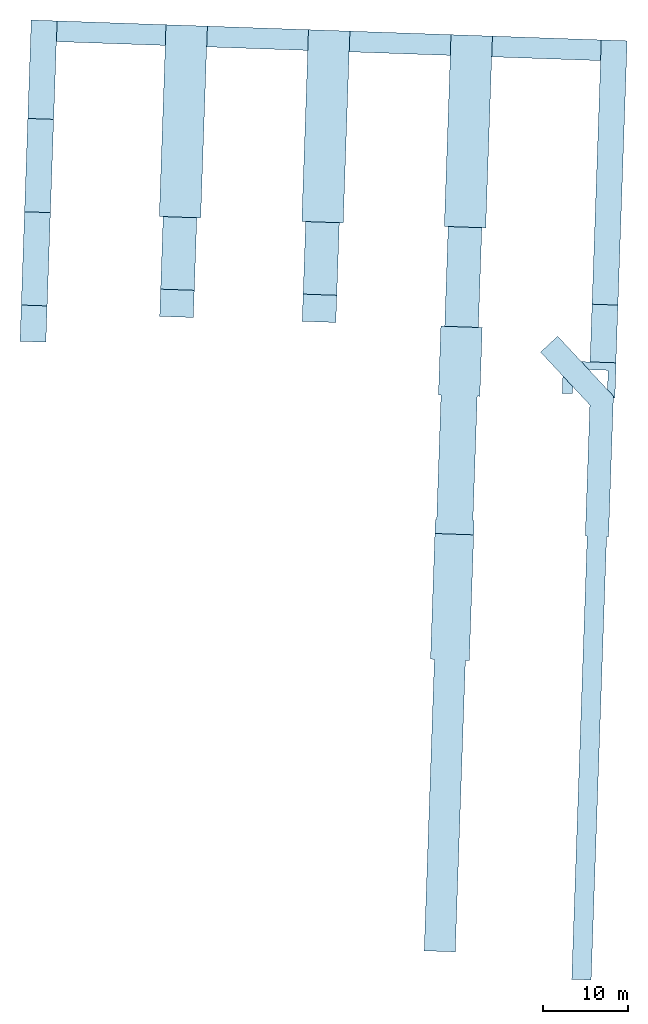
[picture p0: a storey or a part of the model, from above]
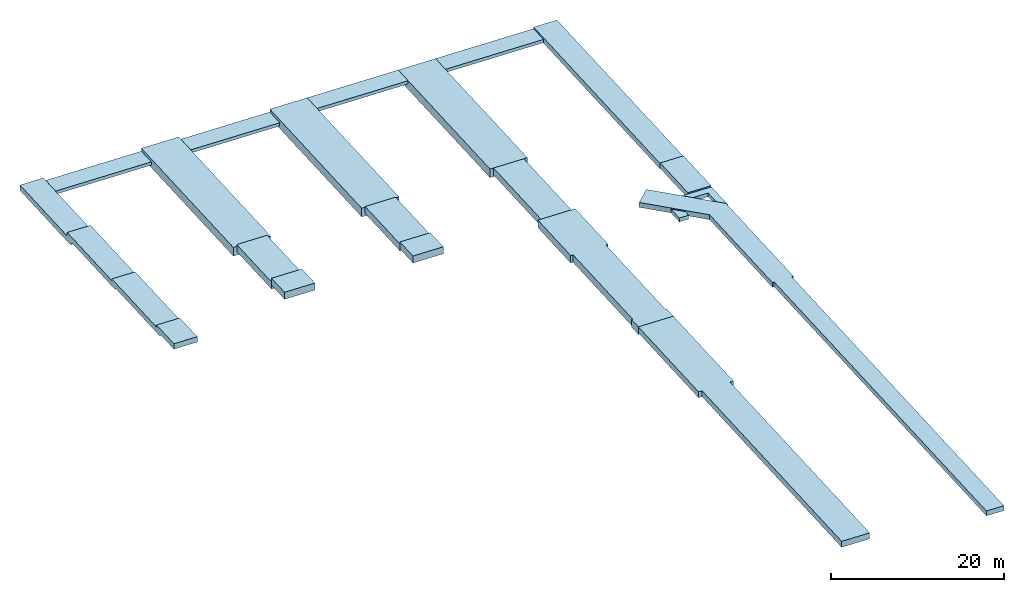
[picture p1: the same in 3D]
Properties of the parts of a building model (IFC2X3), part 1 of 2

# File
Description: ViewDefinition [CoordinationView_V2.0, QuantityTakeOffAddOnView]
File name: 09535.00
Time: 2016-01-25T00:34:02
Written by: The EXPRESS Data Manager Version 5.02.0100.07 : 28 Aug 2013
Made in: 20150702_1515(x64) - Exporter 15.5.0.0 - Alternate UI 15.5.0.0
Comment: STEP Physical File produced by: The EXPRESS Data Manager Version 5.02.0100.07 : 28 Aug 2013 * Module: EDMstepFileFactory/EDMstandAlone * Creation date: Mon Jan 25 00:34:02 2016 * Host: WawanHP * Database: C:\Users\wawan\AppData\Local\Temp\{A744FDD4-6852-4056-9BD2-3EB6C8955B42}\ifc * Database version: 5507 * Database creation date: Mon Jan 25 00:33:48 2016 * Schema: IFC2X3 * Model: DataRepository.ifc * Model creation date: Mon Jan 25 00:33:49 2016 * Header model: DataRepository.ifc_HeaderModel * Header model creation date: Mon Jan 25 00:33:49 2016 * EDMuser: sdai-user * EDMgroup: sdai-group * License ID and type: 5605 : Permanent license. Expiry date: * EDMstepFileFactory options: 020000

# IfcProject, 09535.00
LongName: PROJECT NAME; Phase: Project Status

# IfcSite, Default
RefLatitude: 43, 10, 4, 799999; RefLongitude: -77, -36, -53, -999999; RefElevation: 0.00393701 ft

# IfcBuilding
Pset_BuildingCommon - NumberOfStoreys: 12

# IfcBuildingStorey (12)
Name | LongName | Elevation (ft)
Potential Ground Water Elevation | Potential Ground Water Elevation | 535
Ground Floor | Ground Floor | 543.5
Exist Garage - Ground Level | Exist Garage - Ground Level | 544.75
1st Floor | 1st Floor | 556.833
Existing Garage - 1st Level | Existing Garage - 1st Level | 557
Existing Garage - 2nd Level | Existing Garage - 2nd Level | 567
2nd Floor | 2nd Floor | 570.167
Existing Garage - 3rd Level | Existing Garage - 3rd Level | 577
Existing Garage - 4th Level | Existing Garage - 4th Level | 587
Existing Garage - 5th Level | Existing Garage - 5th Level | 597
Existing Garage - Roof Level | Existing Garage - Roof Level | 607
Exhaust Structure Roof | Exhaust Structure Roof | 617

# IfcSpace (5)
In: Exist Garage - Ground Level
InteriorOrExteriorSpace: INTERNAL
Pset_SpaceCommon - Category: Rooms
Name | LongName | Reference | NetFloorArea (ft2) = GrossFloorArea (ft2) | Height (ft) | GrossPerimeter (ft) | GrossVolume (ft3)
03 | FUEL VAULT | FUEL VAULT 03 | 330 | 10.1894 | 82 | 3362.49
07 | FUEL TANK ROOM #2 | FUEL TANK ROOM #2 07 | 715.313 | 10 | 118.188 | 7153.13
08 | FUEL TANK ROOM #3 | FUEL TANK ROOM #3 08 | 715.313 | 10 | 118.188 | 7153.13
06 | FUEL TANK ROOM #1 | FUEL TANK ROOM #1 06 | 990.656 | 10 | 146.25 | 9906.56
05 | GENERATOR ROOM #2 | GENERATOR ROOM #2 05 | 3270.48 | 10 | 299.545 | 32704.8

# IfcBeam: 05_HSS-Hollow Structural Section:HSS6x6x5/16:1370025 (28)
Classification: B10 Superstructure (Uniformat); Material: Metal - Steel - ASTM A500 - Grade B - Rectangular and Square
BaseQuantities - CrossSectionArea: 0.0446321 ft2
Pset_BeamCommon - LoadBearing: yes; IsExternal: no; Reference: 05_HSS-Hollow Structural Section:HSS6x6x5/16
Name (05_HSS-Hollow Structural Section:HSS6x6x5/16:...) | In | Length (ft) | OuterSurfaceArea (ft2) | GrossVolume (ft3) | Slope (deg) | Span (ft)
1370108 | Existing Garage - 1st Level | 3.86772 | 14.3267 | 0.172628 | 0 | 3.83333
1370170 | Existing Garage - 1st Level | 3.61954 | 13.4132 | 0.161551 | 0 | 3.91667
1370202 | Existing Garage - 1st Level | 6.41667 | 23.7097 | 0.286395 | 0 | 7
1370308 | Existing Garage - 2nd Level | 6.41667 | 23.7097 | 0.286395 | 0 | 7
1370480 | Existing Garage - 3rd Level | 6.41667 | 23.7097 | 0.286395 | 0 | 7
1370505 | Existing Garage - 4th Level | 6.41667 | 23.7097 | 0.286395 | 0 | 7
1370530 | Existing Garage - 5th Level | 6.41667 | 23.7097 | 0.286395 | 0 | 7
1370555 | Existing Garage - Roof Level | 6.41667 | 23.7097 | 0.286395 | 0 | 7
1370578 | Exhaust Structure Roof | 4.32221 | 15.9998 | 0.192913 | 1.45636 | 4.91826
1370579 | Exhaust Structure Roof | 4.32221 | 15.9998 | 0.192913 | 1.45636 | 4.91826
1370580 | Exhaust Structure Roof | 6.41667 | 23.7097 | 0.286395 | 0 | 7
1370677 | Exhaust Structure Roof | 6.96462 | 25.7268 | 0.310852 | 0 | 7
1370727 | Exhaust Structure Roof | 4.32238 | 16.0004 | 0.19292 | 1.45636 | 4.91826
1433487 | Existing Garage - 2nd Level | 3.86772 | 14.3267 | 0.172628 | 0 | 3.83333
1433488 | Existing Garage - 2nd Level | 3.61954 | 13.4132 | 0.161551 | 0 | 3.91667
1433492 | Existing Garage - 3rd Level | 3.86772 | 14.3267 | 0.172628 | 0 | 3.83333
1433493 | Existing Garage - 3rd Level | 3.61954 | 13.4132 | 0.161551 | 0 | 3.91667
1433495 | Existing Garage - 4th Level | 3.86772 | 14.3267 | 0.172628 | 0 | 3.83333
1433496 | Existing Garage - 4th Level | 3.61954 | 13.4132 | 0.161551 | 0 | 3.91667
1433498 | Existing Garage - 5th Level | 3.86772 | 14.3267 | 0.172628 | 0 | 3.83333
1433499 | Existing Garage - 5th Level | 3.61954 | 13.4132 | 0.161551 | 0 | 3.91667
1433501 | Existing Garage - Roof Level | 3.86772 | 14.3267 | 0.172628 | 0 | 3.83333
1528579 | Existing Garage - 1st Level | 3.61954 | 13.4132 | 0.161551 | 0 | 3.91667
1528762 | Existing Garage - 2nd Level | 3.61954 | 13.4132 | 0.161551 | 0 | 3.91667
1528766 | Existing Garage - 3rd Level | 3.61954 | 13.4132 | 0.161551 | 0 | 3.91667
1528768 | Existing Garage - 4th Level | 3.61954 | 13.4132 | 0.161551 | 0 | 3.91667
1528770 | Existing Garage - 5th Level | 3.61954 | 13.4132 | 0.161551 | 0 | 3.91667
1528772 | Existing Garage - Roof Level | 3.70232 | 13.7179 | 0.165245 | 0 | 3.91667

# IfcBeam: 05_W-Wide Flange:W8X13:1531903, 05_W-Wide Flange:W8X13:1531986
In: Exist Garage - Ground Level
Classification: B10 Superstructure (Uniformat); Material: Metal - Steel - ASTM A992
BaseQuantities - GrossVolume: 0.188646 ft3
Pset_BeamCommon - LoadBearing: yes; IsExternal: no; Slope: 0 deg; Reference: 05_W-Wide Flange:W8X13; Span: 7.75 ft

# IfcBeam: Concrete-Rectangular Beam:34" x 10"w:1504024, Concrete-Rectangular Beam:34" x 10"w:1504014
In: 1st Floor
Classification: B10 Superstructure (Uniformat); Material: Concrete - Cast-in-Place Concrete
BaseQuantities - Length: 16.3333 ft; CrossSectionArea: 2.36111 ft2; OuterSurfaceArea: 124.5 ft2; GrossVolume: 154.259 ft3
Pset_BeamCommon - LoadBearing: yes; IsExternal: no; Slope: 0 deg; Reference: Concrete-Rectangular Beam:34" x 10"w; Span: 74.5 ft

# IfcBeam: Concrete-Rectangular Beam:8" x 15"w:1394106 (41)
Classification: B10 Superstructure (Uniformat); Material: Concrete - Cast-in-Place Concrete
Pset_BeamCommon - LoadBearing: yes; IsExternal: no; Slope: 0 deg; Reference: Concrete-Rectangular Beam:8" x 15"w
Name (Concrete-Rectangular Beam:8" x 15"w:...) | In | GrossVolume (ft3) | Span (ft)
1397949 | Existing Garage - 1st Level | 9.58333 | 11.5
1398018 | Existing Garage - 1st Level | 12.0833 | 14.5
1399332 | Existing Garage - 1st Level | 12.0833 | 14.5
1399372 | Existing Garage - 1st Level | 12.0833 | 14.5
1399498 | Existing Garage - 1st Level | 12.0833 | 14.5
1399691 | Existing Garage - 2nd Level | 9.58333 | 11.5
1399711 | Existing Garage - 2nd Level | 12.0833 | 14.5
1399728 | Existing Garage - 2nd Level | 12.0833 | 14.5
1399790 | Existing Garage - 2nd Level | 12.0833 | 14.5
1399858 | Existing Garage - 2nd Level | 12.0833 | 14.5
1399950 | Existing Garage - 2nd Level | 9.58333 | 11.5
1399997 | Existing Garage - 2nd Level | 9.58333 | 11.5
1400354 | Existing Garage - 3rd Level | 9.58333 | 11.5
1400356 | Existing Garage - 3rd Level | 12.0833 | 14.5
1400358 | Existing Garage - 3rd Level | 12.0833 | 14.5
1400360 | Existing Garage - 3rd Level | 12.0833 | 14.5
1400362 | Existing Garage - 3rd Level | 12.0833 | 14.5
1400364 | Existing Garage - 3rd Level | 9.58333 | 11.5
1400376 | Existing Garage - 4th Level | 9.58333 | 11.5
1400378 | Existing Garage - 4th Level | 12.0833 | 14.5
1400380 | Existing Garage - 4th Level | 12.0833 | 14.5
1400382 | Existing Garage - 4th Level | 12.0833 | 14.5
1400384 | Existing Garage - 4th Level | 12.0833 | 14.5
1400386 | Existing Garage - 4th Level | 9.58333 | 11.5
1400392 | Existing Garage - 5th Level | 9.58333 | 11.5
1400394 | Existing Garage - 5th Level | 12.0833 | 14.5
1400396 | Existing Garage - 5th Level | 12.0833 | 14.5
1400398 | Existing Garage - 5th Level | 12.0833 | 14.5
1400400 | Existing Garage - 5th Level | 12.0833 | 14.5
1400402 | Existing Garage - 5th Level | 9.58333 | 11.5
1400408 | Existing Garage - Roof Level | 9.58333 | 11.5
1400410 | Existing Garage - Roof Level | 12.0833 | 14.5
1400412 | Existing Garage - Roof Level | 12.0833 | 14.5
1400414 | Existing Garage - Roof Level | 12.0833 | 14.5
1400416 | Existing Garage - Roof Level | 12.0833 | 14.5
1400418 | Existing Garage - Roof Level | 9.58333 | 11.5
1401314 | Existing Garage - 2nd Level | 1.75521 | 11.5
1401318 | Existing Garage - 3rd Level | 9.36111 | 11.5
1401321 | Existing Garage - 4th Level | 9.36111 | 11.5
1401324 | Existing Garage - 5th Level | 9.36111 | 11.5
1401327 | Existing Garage - Roof Level | 9.36111 | 11.5

# IfcBeam: Concrete-Rectangular Beam:8" x 19"w:1503866, Concrete-Rectangular Beam:8" x 19"w:1503799
In: Existing Garage - 1st Level
Classification: B10 Superstructure (Uniformat); Material: Concrete - Cast-in-Place Concrete
BaseQuantities - GrossVolume: 73.7083 ft3
Pset_BeamCommon - LoadBearing: yes; IsExternal: no; Slope: 0 deg; Reference: Concrete-Rectangular Beam:8" x 19"w; Span: 74.5 ft

# IfcBeam: Concrete-Rectangular Beam:8" x 8"w:1397341 (51)
Classification: B10 Superstructure (Uniformat); Material: Concrete - Cast-in-Place Concrete
Pset_BeamCommon - LoadBearing: yes; IsExternal: no; Slope: 0 deg; Reference: Concrete-Rectangular Beam:8" x 8"w
Name (Concrete-Rectangular Beam:8" x 8"w:...) | In | GrossVolume (ft3) | Span (ft) | Length (ft) | CrossSectionArea (ft2) | OuterSurfaceArea (ft2)
1394046 | Existing Garage - 1st Level | 0.333333 | 1.75
1395802 | Existing Garage - 1st Level | 0.333333 | 1.75
1395895 | Existing Garage - 1st Level | 0.333333 | 1.75
1396028 | Existing Garage - 1st Level | 0.333333 | 1.75
1396963 | Existing Garage - 2nd Level | 0.333333 | 1.75
1397521 | Existing Garage - 1st Level | 0.333333 | 0.75
1398702 | Existing Garage - 1st Level | 0.333333 | 1.75
1398878 | Existing Garage - 1st Level | 0.333333 | 0.75
1398900 | Existing Garage - 1st Level | 0.333333 | 0.75
1399439 | Existing Garage - 1st Level | 0.333333 | 1.75
1399446 | Existing Garage - 1st Level | 0.333333 | 1.75
1399704 | Existing Garage - 2nd Level | 0.666667 | 3.5 | 0.75 | 0.444444 | 2.88889
1399721 | Existing Garage - 2nd Level | 0.666667 | 4.25 | 0.75 | 0.444444 | 2.88889
1399783 | Existing Garage - 2nd Level | 0.666667 | 4.91667 | 0.75 | 0.444444 | 2.88889
1399851 | Existing Garage - 2nd Level | 0.666667 | 4 | 0.75 | 0.444444 | 2.88889
1399895 | Existing Garage - 2nd Level | 0.666667 | 3.5 | 0.75 | 0.444444 | 2.88889
1399990 | Existing Garage - 2nd Level | 0.708333 | 4
1400352 | Existing Garage - 3rd Level | 0.333333 | 1.75
1400355 | Existing Garage - 3rd Level | 0.666667 | 3.5 | 0.75 | 0.444444 | 2.88889
1400357 | Existing Garage - 3rd Level | 0.666667 | 4.25 | 0.75 | 0.444444 | 2.88889
1400359 | Existing Garage - 3rd Level | 0.666667 | 4.91667 | 0.75 | 0.444444 | 2.88889
1400361 | Existing Garage - 3rd Level | 0.666667 | 4 | 0.75 | 0.444444 | 2.88889
1400363 | Existing Garage - 3rd Level | 0.666667 | 3.5 | 0.75 | 0.444444 | 2.88889
1400365 | Existing Garage - 3rd Level | 0.888889 | 4 | 0.75 | 0.444444 | 2.88889
1400374 | Existing Garage - 4th Level | 0.333333 | 1.75
1400377 | Existing Garage - 4th Level | 0.666667 | 3.5 | 0.75 | 0.444444 | 2.88889
1400379 | Existing Garage - 4th Level | 0.666667 | 4.25 | 0.75 | 0.444444 | 2.88889
1400381 | Existing Garage - 4th Level | 0.666667 | 4.91667 | 0.75 | 0.444444 | 2.88889
1400383 | Existing Garage - 4th Level | 0.666667 | 4 | 0.75 | 0.444444 | 2.88889
1400385 | Existing Garage - 4th Level | 0.666667 | 3.5 | 0.75 | 0.444444 | 2.88889
1400387 | Existing Garage - 4th Level | 0.888889 | 4 | 0.75 | 0.444444 | 2.88889
1400390 | Existing Garage - 5th Level | 0.333333 | 1.75
1400393 | Existing Garage - 5th Level | 0.666667 | 3.5 | 0.75 | 0.444444 | 2.88889
1400395 | Existing Garage - 5th Level | 0.666667 | 4.25 | 0.75 | 0.444444 | 2.88889
1400397 | Existing Garage - 5th Level | 0.666667 | 4.91667 | 0.75 | 0.444444 | 2.88889
1400399 | Existing Garage - 5th Level | 0.666667 | 4 | 0.75 | 0.444444 | 2.88889
1400401 | Existing Garage - 5th Level | 0.666667 | 3.5 | 0.75 | 0.444444 | 2.88889
1400403 | Existing Garage - 5th Level | 0.888889 | 4 | 0.75 | 0.444444 | 2.88889
1400406 | Existing Garage - Roof Level | 0.333333 | 1.75
1400409 | Existing Garage - Roof Level | 0.666667 | 3.5 | 0.75 | 0.444444 | 2.88889
1400411 | Existing Garage - Roof Level | 0.666667 | 4.25 | 0.75 | 0.444444 | 2.88889
1400413 | Existing Garage - Roof Level | 0.666667 | 4.91667 | 0.75 | 0.444444 | 2.88889
1400415 | Existing Garage - Roof Level | 0.666667 | 4 | 0.75 | 0.444444 | 2.88889
1400417 | Existing Garage - Roof Level | 0.666667 | 3.5 | 0.75 | 0.444444 | 2.88889
1400419 | Existing Garage - Roof Level | 0.888889 | 4 | 0.75 | 0.444444 | 2.88889
1401216 | Existing Garage - 2nd Level | 0.333333 | 1.75
1401315 | Existing Garage - 2nd Level | 0.0625 | 1.75
1401319 | Existing Garage - 3rd Level | 0.333333 | 1.75
1401322 | Existing Garage - 4th Level | 0.333333 | 1.75
1401325 | Existing Garage - 5th Level | 0.333333 | 1.75
1401328 | Existing Garage - Roof Level | 0.333333 | 1.75

# IfcBeam: Precast-Rectangular Beam:10 x 42:1283472 (4)
In: Existing Garage - 1st Level
Classification: B10 Superstructure (Uniformat); Material: Concrete - Precast Concrete - Normal Weight - 5 ksi
Pset_BeamCommon - LoadBearing: yes; IsExternal: no; Reference: Precast-Rectangular Beam:10 x 42
Name (Precast-Rectangular Beam:10 x 42:...) | GrossVolume (ft3) | Slope (deg) | Span (ft)
1283546 | 47.3958 | 0 | 18.3333
1283556 | 47.3958 | 0 | 18.3333
1283566 | 47.3958 | 0 | 18.3333
1284165 | 47.3682 | 0.15626 | 18.3334

# IfcBeam: Precast-Rectangular Beam:12 x 42 (47 w/ 5" Conc Slab):1301792 (2)
In: Existing Garage - 1st Level
Classification: B10 Superstructure (Uniformat); Material: Concrete - Precast Concrete - Normal Weight - 5 ksi
BaseQuantities - GrossVolume: 185.073 ft3
Pset_BeamCommon - LoadBearing: yes; IsExternal: no; Reference: Precast-Rectangular Beam:12 x 42 (47 w/ 5" Conc Slab); Span: 55.0041 ft; Slope: 0.69788 deg
Name (Precast-Rectangular Beam:12 x 42 (47 w/ 5" Conc Slab):...)
1301706
1301818

# IfcBeam: Precast-Rectangular Beam:15 x 28 (33 w/ 5" Conc Slab):1280240 (64)
In: Existing Garage - 1st Level
Classification: B10 Superstructure (Uniformat); Material: Concrete - Precast Concrete - Normal Weight - 5 ksi
Pset_BeamCommon - LoadBearing: yes; IsExternal: no; Reference: Precast-Rectangular Beam:15 x 28 (33 w/ 5" Conc Slab)
Name (Precast-Rectangular Beam:15 x 28 (33 w/ 5" Conc Slab):...) | GrossVolume (ft3) | Slope (deg) | Span (ft)
1280257 | 154.75 | 0 | 55
1280592 | 154.75 | 0 | 55
1280607 | 154.75 | 0 | 55
1280621 | 154.75 | 0 | 55
1280716 | 154.314 | 0.229234 | 55.0004
1280799 | 154.314 | 0.229234 | 55.0004
1280810 | 154.314 | 0.229234 | 55.0004
1280820 | 154.314 | 0.229234 | 55.0004
1280868 | 154.288 | 0.489589 | 55.002
1280934 | 154.288 | 0.489589 | 55.002
1280945 | 154.288 | 0.489589 | 55.002
1280955 | 154.288 | 0.489589 | 55.002
1282232 | 154.264 | 0.749947 | 55.0047
1282288 | 154.264 | 0.749947 | 55.0047
1282299 | 154.264 | 0.749947 | 55.0047
1282309 | 154.264 | 0.749947 | 55.0047
1282385 | 154.244 | 1.02064 | 55.0087
1282429 | 154.244 | 1.02064 | 55.0087
1282440 | 154.244 | 1.02064 | 55.0087
1282450 | 154.244 | 1.02064 | 55.0087
1282618 | 49.3619 | 0.763831 | 18.0016
1282689 | 40.6545 | 2.74462 | 15.0173
1282771 | 155.395 | 0.354181 | 55.0011
1282844 | 49.3228 | 1.27272 | 18.0044
1282931 | 40.7223 | 1.29815 | 15.0039
1283005 | 49.4265 | 0.763831 | 18.0016
1283006 | 40.6741 | 0.57291 | 15.0007
1283074 | 46.2054 | 2.0985 | 18.0121
1283138 | 46.2083 | 2.06677 | 18.0117
1283195 | 156.489 | 0.354181 | 55.0011
1283234 | 156.488 | 0.354181 | 55.0011
1283263 | 155.395 | 0.354181 | 55.0011
1283302 | 154.264 | 0.749947 | 55.0047
1283362 | 154.264 | 0.749947 | 55.0047
1283372 | 154.322 | 0.15626 | 55.0002
1283397 | 154.322 | 0.15626 | 55.0002
1283666 | 37.446 | 2.13656 | 15.0104
1283734 | 46.2807 | 1.30451 | 18.0047
1283751 | 46.2839 | 1.27237 | 18.0044
1283845 | 46.2054 | 2.0985 | 18.0121
1283866 | 46.2083 | 2.06677 | 18.0117
1283942 | 37.5862 | 0.763831 | 15.0013
1287775 | 37.5655 | 0.954709 | 15.0021
1300521 | 154.254 | 0.874815 | 55.0064
1300537 | 154.23 | 1.21838 | 55.0124
1300643 | 154.254 | 0.874815 | 55.0064
1300644 | 154.23 | 1.21838 | 55.0124
1300707 | 81.2744 | 1.48885 | 30.0102
1300839 | 155.353 | 0.812421 | 55.0055
1300944 | 81.3761 | 0.419217 | 30.0008
1301059 | 156.467 | 0.58307 | 55.0028
1301120 | 81.2744 | 1.48885 | 30.0102
1301121 | 155.353 | 0.812421 | 55.0055
1301122 | 156.467 | 0.58307 | 55.0028
1301165 | 154.296 | 0.406193 | 55.0014
1301260 | 154.308 | 0.291616 | 55.0007
1301422 | 154.296 | 0.406193 | 55.0014
1301423 | 154.308 | 0.291616 | 55.0007
1301474 | 110.593 | 0 | 40.0008
1301554 | 154.34 | 0 | 55
1301630 | 110.59 | 0 | 40.0008
1301631 | 154.34 | 0 | 55
1301853 | 154.23 | 1.21838 | 55.0124
1301948 | 154.251 | 0.916537 | 55.007

# IfcBeam: Precast-Rectangular Beam:24 x 12:1284017 (2)
In: Existing Garage - 1st Level
Classification: B10 Superstructure (Uniformat); Material: Concrete - Precast Concrete - Normal Weight - 5 ksi
Pset_BeamCommon - LoadBearing: yes; IsExternal: no; Reference: Precast-Rectangular Beam:24 x 12
Name (Precast-Rectangular Beam:24 x 12:...) | GrossVolume (ft3) | Span (ft) | Slope (deg)
1283994 | 69.1572 | 36.6672 | 0.29689
1284086 | 69.164 | 36.6667 | 0.0781305

# IfcBuildingElementProxy: 18', Pavement Stripe:18':1308312
In: Exist Garage - Ground Level
Material: Parking Stripe
Pset_BuildingElementProxyCommon - Reference: Pavement Stripe:18'

# IfcBuildingElementProxy: Convault Oil Tank (3)
Type - Material: Conc Shell
Pset_BuildingElementProxyCommon - Reference: Convault Oil Tank:Convault Oil Tank
Name (Convault Oil Tank:Convault Oil Tank:...) | In
1333229 | 06
1333512 | 07
1334021 | 08

# IfcBuildingElementProxy: URMC Exist Garage A1-G4 1st Floor (6)
Type - Material: Conc Slab
Pset_BuildingElementProxyCommon - Reference: URMC Exist Garage A1-G4 1st Floor:URMC Exist Garage A1-G4 1st Floor
Name (URMC Exist Garage A1-G4 1st Floor:URMC Exist Garage A1-G4 1st Floor:...) | In
1289256 | Existing Garage - 1st Level
1296614 | Existing Garage - 2nd Level
1296649 | Existing Garage - 3rd Level
1296673 | Existing Garage - 4th Level
1296683 | Existing Garage - 5th Level
1299379 | Existing Garage - Roof Level

# IfcBuildingElementProxy: URMC Exist Garage A15-D18, URMC Exist Garage A15-D18:URMC Exist Garage A15-D18:1276843
In: Exist Garage - Ground Level
Type - Material: Conc Slab
Pset_BuildingElementProxyCommon - Reference: URMC Exist Garage A15-D18:URMC Exist Garage A15-D18

# IfcBuildingElementProxy: URMC Exist Garage A15-G18 1st Floor, URMC Exist Garage A15-G18 1st Floor:URMC Exist Garage A15-G18 1st Floor:1292425
In: Existing Garage - 1st Level
Type - Material: Conc Slab
Pset_BuildingElementProxyCommon - Reference: URMC Exist Garage A15-G18 1st Floor:URMC Exist Garage A15-G18 1st Floor

# IfcBuildingElementProxy: URMC Exist Garage A15-G18 2nd Floor (5)
Type - Material: Conc Slab
Pset_BuildingElementProxyCommon - Reference: URMC Exist Garage A15-G18 2nd Floor:URMC Exist Garage A15-G18 2nd Floor
Name (URMC Exist Garage A15-G18 2nd Floor:URMC Exist Garage A15-G18 2nd Floor:...) | In
1297690 | Existing Garage - 2nd Level
1297964 | Existing Garage - 3rd Level
1297972 | Existing Garage - 4th Level
1297980 | Existing Garage - 5th Level
1299347 | Existing Garage - Roof Level

# IfcBuildingElementProxy: URMC Exist Garage A4-D14 1st Floor (5)
Type - Material: Conc Slab
Pset_BuildingElementProxyCommon - Reference: URMC Exist Garage A4-D14 1st Floor:URMC Exist Garage A4-D14 1st Floor
Name (URMC Exist Garage A4-D14 1st Floor:URMC Exist Garage A4-D14 1st Floor:...) | In
1296490 | Existing Garage - 1st Level
1296648 | Existing Garage - 2nd Level
1296672 | Existing Garage - 3rd Level
1296682 | Existing Garage - 4th Level
1298009 | Existing Garage - 5th Level

# IfcBuildingElementProxy: URMC Exist Garage D2-G18, URMC Exist Garage D2-G18:URMC Exist Garage D2-G18:1278203
In: Exist Garage - Ground Level
Type - Material: Conc Slab
Pset_BuildingElementProxyCommon - Reference: URMC Exist Garage D2-G18:URMC Exist Garage D2-G18

# IfcBuildingElementProxy: URMC Exist Garage D4-G15 1st Floor (5)
Type - Material: Conc Slab
Pset_BuildingElementProxyCommon - Reference: URMC Exist Garage D4-G15 1st Floor:URMC Exist Garage D4-G15 1st Floor
Name (URMC Exist Garage D4-G15 1st Floor:URMC Exist Garage D4-G15 1st Floor:...) | In
1291389 | Existing Garage - 1st Level
1298077 | Existing Garage - 2nd Level
1298085 | Existing Garage - 3rd Level
1298093 | Existing Garage - 4th Level
1298101 | Existing Garage - 5th Level

# IfcBuildingElementProxy: URMC Garage Add 1st Fl, URMC Garage Add 1st Fl:URMC Garage Add 1st Fl:1282121
In: Existing Garage - 1st Level
Pset_BuildingElementProxyCommon - Reference: URMC Garage Add 1st Fl:URMC Garage Add 1st Fl

# IfcBuildingElementProxy: URMC Garage Add 2nd-5th Fl (5)
Type - Material: Conc Slab
Pset_BuildingElementProxyCommon - Reference: URMC Garage Add 2nd-5th Fl:URMC Garage Add 2nd-5th Fl
Name (URMC Garage Add 2nd-5th Fl:URMC Garage Add 2nd-5th Fl:...) | In
1299206 | Existing Garage - 2nd Level
1299295 | Existing Garage - 3rd Level
1299303 | Existing Garage - 4th Level
1299311 | Existing Garage - 5th Level
1299319 | Existing Garage - Roof Level

# IfcBuildingElementProxy: URMC Garage Add Gr Fl, URMC Garage Add Gr Fl:URMC Garage Add Gr Fl:1270194
In: Exist Garage - Ground Level
Type - Material: Conc Slab
Pset_BuildingElementProxyCommon - Reference: URMC Garage Add Gr Fl:URMC Garage Add Gr Fl

# IfcBuildingElementProxy: URMC Garage gr fl ramp1, URMC Garage gr fl ramp1:URMC Garage gr fl ramp1:1226104
In: Exist Garage - Ground Level
Pset_BuildingElementProxyCommon - Reference: URMC Garage gr fl ramp1:URMC Garage gr fl ramp1

# IfcColumn: 13 x 13 (2)
In: Exist Garage - Ground Level
Type - ElementType: 13 x 13; PredefinedType: COLUMN; Classification: B10 Superstructure (Uniformat); Material: Concrete - Cast-in-Place Concrete
Pset_ColumnCommon - LoadBearing: yes; IsExternal: no; Reference: Concrete-Square-Column:13 x 13
Name (Concrete-Square-Column:13 x 13:...) | GrossVolume (ft3)
1409713 | 2.34722
1409932 | 2.33956

# IfcColumn: 16 x 24 (2)
In: Exist Garage - Ground Level
Type - ElementType: 16 x 24; PredefinedType: COLUMN; Classification: B10 Superstructure (Uniformat); Material: Concrete - Cast-in-Place Concrete
BaseQuantities - GrossVolume: 166 ft3
Pset_ColumnCommon - LoadBearing: yes; IsExternal: no; Reference: Concrete-Rectangular-Column:16 x 24
Name (Concrete-Rectangular-Column:16 x 24:...)
1210074
1210206

# IfcColumn: 18 x 24, Concrete-Rectangular-Column:18 x 24:1210865
In: Exist Garage - Ground Level
Type - ElementType: 18 x 24; PredefinedType: COLUMN; Classification: B10 Superstructure (Uniformat); Material: Concrete - Cast-in-Place Concrete
BaseQuantities - GrossVolume: 185.25 ft3
Pset_ColumnCommon - LoadBearing: yes; IsExternal: no; Reference: Concrete-Rectangular-Column:18 x 24

# IfcColumn: 18 x 30, Concrete-Rectangular-Column:18 x 30:1210440
In: Exist Garage - Ground Level
Type - ElementType: 18 x 30; PredefinedType: COLUMN; Classification: B10 Superstructure (Uniformat); Material: Concrete - Cast-in-Place Concrete
BaseQuantities - GrossVolume: 233.438 ft3
Pset_ColumnCommon - LoadBearing: yes; IsExternal: no; Reference: Concrete-Rectangular-Column:18 x 30

# IfcColumn: 20 x 32, Concrete-Rectangular-Column:20 x 32:1211124
In: Exist Garage - Ground Level
Type - ElementType: 20 x 32; PredefinedType: COLUMN; Classification: B10 Superstructure (Uniformat); Material: Concrete - Cast-in-Place Concrete
BaseQuantities - GrossVolume: 276.667 ft3
Pset_ColumnCommon - LoadBearing: yes; IsExternal: no; Reference: Concrete-Rectangular-Column:20 x 32

# IfcColumn: 24 x 24 (120)
In: Exist Garage - Ground Level
Type - ElementType: 24 x 24; PredefinedType: COLUMN; Classification: B10 Superstructure (Uniformat); Material: Concrete - Cast-in-Place Concrete
Pset_ColumnCommon - Reference: Concrete-Square-Column:24 x 24; LoadBearing: yes; IsExternal: no
Name (Concrete-Square-Column:24 x 24:...) | GrossVolume (ft3)
1204788 | 249
1207221 | 249
1207248 | 249
1207258 | 249
1207268 | 249
1207278 | 249
1207288 | 242.27
1207298 | 242.415
1207308 | 242.415
1207318 | 235.54
1207328 | 221.432
1207551 | 259.48
1207563 | 259.48
1207573 | 253
1207583 | 253
1207597 | 249.799
1207607 | 249.799
1207617 | 249
1207660 | 263.32
1207682 | 263.32
1207692 | 263.32
1207704 | 256.68
1207714 | 249.68
1207726 | 249
1207780 | 260
1207792 | 260
1207802 | 260
1207814 | 258.68
1207824 | 255
1207834 | 249
1207873 | 260
1207931 | 260
1207943 | 260
1207955 | 260
1207965 | 260
1207973 | 259
1208031 | 220.226
1208041 | 226.67
1208053 | 229.198
1208065 | 229.198
1208075 | 229.198
1208085 | 227.969
1208095 | 254.437
1210066 | 249
1210084 | 249
1210094 | 249
1210104 | 249
1210114 | 249
1210122 | 249
1210136 | 249
1210146 | 249
1210156 | 249
1210164 | 249
1210174 | 249
1210184 | 249
1210194 | 249
1210216 | 249
1210246 | 249
1210258 | 249
1210268 | 249
1210278 | 249
1210288 | 249
1210298 | 249
1210308 | 249
1210318 | 249
1210328 | 249
1210338 | 249
1210348 | 249
1210360 | 249
1210374 | 249
1210384 | 249
1210394 | 249
1210404 | 249
1210490 | 249
1210502 | 249
1210516 | 249
1210526 | 249
1210538 | 249
1210546 | 249
1210556 | 249
1210566 | 249
1210576 | 249
1210586 | 249
1210598 | 249
1210608 | 249
1210618 | 249
1210628 | 249
1210640 | 249
1210650 | 249
1210678 | 249
1210686 | 249
1210696 | 249
1210706 | 249
1210716 | 249
1210728 | 248.583
1210740 | 248.167
1210750 | 248.583
1210760 | 249
1210772 | 249
1210782 | 249
1210792 | 249
1210802 | 249
1210812 | 249
1210822 | 249
1210832 | 249
1210925 | 248.958
1210935 | 247
1210945 | 249
1210957 | 248.167
1210967 | 249
1210977 | 248.583
1210987 | 248.167
1210997 | 248.583
1211009 | 249
1211019 | 249
1211029 | 249
1211041 | 249
1211053 | 249
1211061 | 249
1254820 | 249

# IfcColumn: 24 x 32, Concrete-Rectangular-Column:24 x 32:1211085
In: Exist Garage - Ground Level
Type - ElementType: 24 x 32; PredefinedType: COLUMN; Classification: B10 Superstructure (Uniformat); Material: Concrete - Cast-in-Place Concrete
BaseQuantities - GrossVolume: 332 ft3
Pset_ColumnCommon - LoadBearing: yes; IsExternal: no; Reference: Concrete-Rectangular-Column:24 x 32

# IfcColumn: HSS6x6x5/16 (4)
Type - ElementType: HSS6x6x5/16; PredefinedType: COLUMN; Classification: B10 Superstructure (Uniformat); Material: Metal - Steel - ASTM A500 - Grade B - Rectangular and Square
BaseQuantities - CrossSectionArea: 0.0446321 ft2
Pset_ColumnCommon - LoadBearing: yes; IsExternal: no; Reference: 05_HSS-Hollow Structural Section-Column:HSS6x6x5/16
Name (05_HSS-Hollow Structural Section-Column:HSS6x6x5/16:...) | In | Length (ft) | OuterSurfaceArea (ft2) | GrossVolume (ft3)
1363478 | Exist Garage - Ground Level | 71.8333 | 264.515 | 3.31495 | Pset_ColumnCommon - Slope: 0 deg
1363479 | Exist Garage - Ground Level | 71.8333 | 264.515 | 3.31495
1370627 | Existing Garage - Roof Level | 9.875 | 36.4401 | 0.455709 | Pset_ColumnCommon - Slope: 0 deg
1370628 | Existing Garage - Roof Level | 9.875 | 36.4401 | 0.455709

# IfcColumn: HSS8X8X1/4 (8)
In: Exist Garage - Ground Level
Type - ElementType: HSS8X8X1/4; PredefinedType: COLUMN; Classification: B10 Superstructure (Uniformat); Material: Metal - Steel - ASTM A500 - Grade B - Rectangular and Square
BaseQuantities - Length: 62.25 ft; CrossSectionArea: 0.0492979 ft2; OuterSurfaceArea: 316.204 ft2; GrossVolume: 3.12929 ft3
Pset_ColumnCommon - LoadBearing: yes; IsExternal: no; Reference: HSS-Hollow Structural Section-Column:HSS8X8X1/4
Name (HSS-Hollow Structural Section-Column:HSS8X8X1/4:...)
1260411 | Pset_ColumnCommon - Slope: 0 deg
1260479
1261423
1261424
1274463
1274473
1274509
1274510

# IfcCovering: Compound Ceiling:Rated Shaft, Compound Ceiling:Rated Shaft:1552368
In: Exist Garage - Ground Level
PredefinedType: CEILING; Classification: C3030220 Suspended Ceilings - Gypsum Board (Uniformat); Material: Finishes - Interior - Gypsum Wall Board_Ceiling 0.0833333 ft, Metal - Stud Layer 0.125 ft, Finishes - Interior - Gypsum Wall Board_Ceiling 0.0520833 ft, Finishes - Interior - Gypsum Wall Board_Ceiling 0.0520833 ft
Pset_CoveringCommon - Reference: Compound Ceiling:Rated Shaft; Finish: Finishes - Interior - Gypsum Wall Board_Ceiling;; TotalThickness: 0.3125 ft
BaseQuantities - GrossCeilingArea: 163.657 ft2

# IfcCurtainWall: Curtain Wall:(Existing) Curtainwall - Blank (19)
Classification: B2020200 Curtain Walls (Uniformat)
Pset_CurtainWallCommon - IsExternal: yes; Reference: Curtain Wall:(Existing) Curtainwall - Blank
Name (Curtain Wall:(Existing) Curtainwall - Blank:...) | In
1227236 | Exist Garage - Ground Level
1227274 | Exist Garage - Ground Level
1227323 | Exist Garage - Ground Level
1228684 | Exist Garage - Ground Level
1243572 | Existing Garage - 1st Level
1250813 | Exist Garage - Ground Level
1251231 | Exist Garage - Ground Level
1251270 | Exist Garage - Ground Level
1252235 | Exist Garage - Ground Level
1254416 | Existing Garage - 1st Level
1254421 | Existing Garage - 1st Level
1254423 | Existing Garage - 1st Level
1254661 | Existing Garage - 1st Level
1359330 | Exist Garage - Ground Level
1359423 | Exist Garage - Ground Level
1359474 | Exist Garage - Ground Level
1512584 | Existing Garage - Roof Level
1512586 | Existing Garage - Roof Level
1512588 | Existing Garage - Roof Level

# IfcDoor: 3'-0" x 7'-0" Metal_5.75" x 4" (3)
In: Exist Garage - Ground Level
Type - ParameterTakesPrecedence: no; Sizeable: no; Material: Door - Hardware, Door - H.M. Panel, Door - H.M. Frame
OverallHeight: 7.33333 ft; OverallWidth: 3.33333 ft
Pset_DoorCommon - IsExternal: no; Reference: HM_Frame_Door_-_Interior_Single_3897:3'-0" x 7'-0" Metal_5.75" x 4"
BaseQuantities - Height: 7 ft; Width: 3 ft; Area: 35.5476 ft2
Name (HM_Frame_Door_-_Interior_Single_3897:3'-0" x 7'-0" Metal_5.75" x 4":...)
1333612
1333663
1333963

# IfcDoor: 6'-0" x 7'-0" Metal_5.75" x 4" (2)
In: Exist Garage - Ground Level
Type - OperationType: DOUBLE_DOOR_SINGLE_SWING; ParameterTakesPrecedence: no; Sizeable: no; Material: Door - Hardware, Door - H.M. Panel, Door - H.M. Frame
Type - Exterior Double Flush:6'-0" x 7'-0" Metal_5.75" x 4":1334051 - PanelOperation: SWINGING
OverallHeight: 7.33333 ft; OverallWidth: 6.33333 ft
Pset_DoorCommon - IsExternal: no; Reference: Exterior Double Flush:6'-0" x 7'-0" Metal_5.75" x 4"
BaseQuantities - Height: 7 ft; Width: 6 ft; Area: 60.9089 ft2
Name (Exterior Double Flush:6'-0" x 7'-0" Metal_5.75" x 4":...)
1334051
1334142

# IfcDoor: 6'-0" x 7'-0" Metal_5.75" x 4", Exterior Double Flush:6'-0" x 7'-0" Metal_5.75" x 4":1334168
In: Exist Garage - Ground Level
Type - OperationType: DOUBLE_DOOR_SINGLE_SWING; ParameterTakesPrecedence: no; Sizeable: no; Material: Door - Hardware, Door - H.M. Panel, Door - H.M. Frame
Type - Exterior Double Flush:6'-0" x 7'-0" Metal_5.75" x 4":1334168 - PanelOperation: SWINGING
OverallHeight: 7.33333 ft; OverallWidth: 6.33333 ft
Pset_DoorCommon - IsExternal: no; Reference: Exterior Double Flush:6'-0" x 7'-0" Metal_5.75" x 4"
BaseQuantities - Height: 7 ft; Width: 6 ft; Area: 60.9089 ft2

# IfcDoor: 8' x 10'-0" (2)
In: Exist Garage - Ground Level
Type - ParameterTakesPrecedence: no; Sizeable: no; Classification: B2030410 Overhead Doors (Uniformat); Material: Metal - Paint Finish - Ivory, Matte
OverallHeight: 8 ft; OverallWidth: 10 ft
Pset_DoorCommon - IsExternal: yes; Reference: Overhead-Rolling:8' x 10'-0"
BaseQuantities - Height: 8 ft; Width: 10 ft; Area: 128.236 ft2
Name (Overhead-Rolling:8' x 10'-0":...)
1359950
1360046

# IfcDoor: Default, 08_Curtain Wall_75G Door Panel:Default:1503109
In: Exist Garage - Ground Level
Type - ParameterTakesPrecedence: no; Sizeable: no; Material: Door Glazing, Metal - Aluminum
OverallHeight: 7 ft; OverallWidth: 3.66667 ft; Classification: B2020200 Curtain Walls (Uniformat)
Pset_DoorCommon - IsExternal: no; Reference: 08_Curtain Wall_75G Door Panel:Default
BaseQuantities - Area: 577.993 ft2

# IfcFooting: E14-18 Grade Beam:E14-18 Grade Beam, E14-18 Grade Beam:E14-18 Grade Beam:1262143
In: Potential Ground Water Elevation
Material: Concrete - Cast-in-Place Concrete

# IfcFooting: E19-E22 Grade Beam1:E19-E22 Grade Beam, E19-E22 Grade Beam1:E19-E22 Grade Beam:1265089
In: Potential Ground Water Elevation
Material: Concrete - Cast-in-Place Concrete

# IfcFooting: E19-E22 Grade Beam2:E19-E22 Grade Beam, E19-E22 Grade Beam2:E19-E22 Grade Beam:1265289
In: Potential Ground Water Elevation
Material: Concrete - Cast-in-Place Concrete

# IfcFooting: E19-E22 Grade Beam3:E19-E22 Grade Beam, E19-E22 Grade Beam3:E19-E22 Grade Beam:1266470
In: Potential Ground Water Elevation
Material: Concrete - Cast-in-Place Concrete

# IfcFooting: E19-E22 Grade Beam4:E19-E22 Grade Beam, E19-E22 Grade Beam4:E19-E22 Grade Beam:1266494
In: Potential Ground Water Elevation
Material: Concrete - Cast-in-Place Concrete

# IfcFooting: E19-E22 Grade Beam:E19-E22 Grade Beam, E19-E22 Grade Beam:E19-E22 Grade Beam:1263224
In: Potential Ground Water Elevation
Material: Concrete - Cast-in-Place Concrete

# IfcFooting: E22-E26 Grade Beam1:E22-E26 Grade Beam, E22-E26 Grade Beam1:E22-E26 Grade Beam:1265101
In: Potential Ground Water Elevation
Material: Concrete - Cast-in-Place Concrete

# IfcFooting: E22-E26 Grade Beam2:E22-E26 Grade Beam, E22-E26 Grade Beam2:E22-E26 Grade Beam:1266482
In: Potential Ground Water Elevation
Material: Concrete - Cast-in-Place Concrete

# IfcFooting: E22-E26 Grade Beam:E22-E26 Grade Beam, E22-E26 Grade Beam:E22-E26 Grade Beam:1263423
In: Potential Ground Water Elevation
Material: Concrete - Cast-in-Place Concrete

# IfcFooting: E5-14 Grade Beam:E5-14 Grade Beam, E5-14 Grade Beam:E5-14 Grade Beam:1262807
In: Potential Ground Water Elevation
Material: Concrete - Cast-in-Place Concrete

# IfcFooting: G19-20 Grade Beam:G19-20 Grade Beam, G19-20 Grade Beam:G19-20 Grade Beam:1263953
In: Potential Ground Water Elevation
Material: Concrete - Cast-in-Place Concrete

# IfcFooting: G21-26 Grade Beam:G21-26 Grade Beam, G21-26 Grade Beam:G21-26 Grade Beam:1264291
In: Potential Ground Water Elevation
Material: Concrete - Cast-in-Place Concrete

# IfcFooting: G26 GG-GD Grade Beam1:G26 GG-GD Grade Beam, G26 GG-GD Grade Beam1:G26 GG-GD Grade Beam:1266529
In: Potential Ground Water Elevation
Material: Concrete - Cast-in-Place Concrete

# IfcFooting: G26 GG-GD Grade Beam:G26 GG-GD Grade Beam, G26 GG-GD Grade Beam:G26 GG-GD Grade Beam:1264705
In: Potential Ground Water Elevation
Material: Concrete - Cast-in-Place Concrete

# IfcFooting: G4-G18 Column Grade Beam:G4-G18 Column Grade Beam, G4-G18 Column Grade Beam:G4-G18 Column Grade Beam:1259190
In: Potential Ground Water Elevation
Material: Concrete - Cast-in-Place Concrete

# IfcFooting: GA G19-26 Grade Beam:GA G19-26 Grade Beam, GA G19-26 Grade Beam:GA G19-26 Grade Beam:1268890
In: Potential Ground Water Elevation
Material: Concrete - Cast-in-Place Concrete

# IfcFooting: SE Stair Footing:SE Stair Footing, SE Stair Footing:SE Stair Footing:1261234
In: Potential Ground Water Elevation
Material: Concrete - Cast-in-Place Concrete

# IfcMember: Curtain Wall:(Existing) Curtainwall - Blank:1245096 (57)
Classification: B2020200 Curtain Walls (Uniformat); Material: Metal - Aluminum
Pset_MemberCommon - LoadBearing: yes; IsExternal: yes; Reference: Rectangular Mullion:Curtainwall - 6" x 6"
Name (Curtain Wall:(Existing) Curtainwall - Blank:...) | In | Span (ft)
2 x 1245096 | Exist Garage - Ground Level | 70.2083
4 x 1245096 | Existing Garage - 1st Level | 63.8958
2 x 1245096 | Existing Garage - 1st Level | 2.98903
2 x 1245096 | Existing Garage - 1st Level | 6.8848
2 x 1245096 | Existing Garage - 1st Level | 6.51584
2 x 1245096 | Existing Garage - 1st Level | 6.88424
2 x 1245096 | Existing Garage - 1st Level | 6.63507
2 x 1245096 | Existing Garage - 1st Level | 2.98893
2 x 1245096 | Existing Garage - 1st Level | 6.51594
2 x 1245096 | Existing Garage - 1st Level | 2.98905
2 x 1245096 | Existing Garage - 1st Level | 6.63504
14 x 1245096 | Exist Garage - Ground Level | 7.25
12 x 1245096 | Exist Garage - Ground Level | 2.75
2 x 1245096 | Exist Garage - Ground Level | 2.58333
1245096 | Existing Garage - Roof Level | 3.75
2 x 1245096 | Existing Garage - Roof Level | 2.58333
1245096 | Existing Garage - Roof Level | 2.9375
1245096 | Existing Garage - Roof Level | 3.64583

# IfcMember: Curtain Wall:(Existing) Curtainwall - Blank:307977 (44)
Classification: B2020200 Curtain Walls (Uniformat); Material: Metal - Aluminum
Pset_MemberCommon - LoadBearing: yes; IsExternal: yes; Reference: Rectangular Mullion:Curtainwall-1-Left Side_Bottom- 2 1/2" x 6"
Name (Curtain Wall:(Existing) Curtainwall - Blank:...) | In | Span (ft)
307977 | Exist Garage - Ground Level | 17.2951
307977 | Exist Garage - Ground Level | 70.2083
2 x 307977 | Exist Garage - Ground Level | 2.36458
2 x 307977 | Exist Garage - Ground Level | 2.26042
307977 | Exist Garage - Ground Level | 4.95833
307977 | Exist Garage - Ground Level | 2.29167
307977 | Exist Garage - Ground Level | 21.0365
307977 | Exist Garage - Ground Level | 72.5
307977 | Exist Garage - Ground Level | 10.875
307977 | Exist Garage - Ground Level | 4.64583
307977 | Exist Garage - Ground Level | 62.25
307977 | Exist Garage - Ground Level | 1.375
307977 | Existing Garage - 1st Level | 18.2299
307977 | Existing Garage - 1st Level | 60.25
307977 | Existing Garage - 1st Level | 10.875
307977 | Existing Garage - 1st Level | 4.64583
307977 | Existing Garage - 1st Level | 50
307977 | Existing Garage - 1st Level | 1.375
2 x 307977 | Exist Garage - Ground Level | 3.79167
3 x 307977 | Exist Garage - Ground Level | 2.375
7 x 307977 | Exist Garage - Ground Level | 7.25
6 x 307977 | Exist Garage - Ground Level | 2.75
307977 | Exist Garage - Ground Level | 3
307977 | Exist Garage - Ground Level | 7.10417
2 x 307977 | Existing Garage - Roof Level | 1.91667
307977 | Existing Garage - Roof Level | 2.83333
307977 | Existing Garage - Roof Level | 2.375

# IfcMember: Curtain Wall:(Existing) Curtainwall - Blank:307979 (44)
Classification: B2020200 Curtain Walls (Uniformat); Material: Metal - Aluminum
Pset_MemberCommon - LoadBearing: yes; IsExternal: yes; Reference: Rectangular Mullion:Curtainwall-2-Right Side_Top-2 1/2" x 6"
Name (Curtain Wall:(Existing) Curtainwall - Blank:...) | In | Span (ft)
307979 | Exist Garage - Ground Level | 17.2951
4 x 307979 | Exist Garage - Ground Level | 2.36458
307979 | Exist Garage - Ground Level | 4.58333
307979 | Exist Garage - Ground Level | 1.91667
307979 | Exist Garage - Ground Level | 21.0365
307979 | Exist Garage - Ground Level | 10.875
307979 | Exist Garage - Ground Level | 72.5
307979 | Exist Garage - Ground Level | 4.64583
307979 | Exist Garage - Ground Level | 1.375
307979 | Exist Garage - Ground Level | 62.25
307979 | Existing Garage - 1st Level | 18.2299
307979 | Existing Garage - 1st Level | 10.875
307979 | Existing Garage - 1st Level | 60.25
307979 | Existing Garage - 1st Level | 4.64583
307979 | Existing Garage - 1st Level | 1.375
307979 | Existing Garage - 1st Level | 50
2 x 307979 | Exist Garage - Ground Level | 4
2 x 307979 | Exist Garage - Ground Level | 2.47917
307979 | Exist Garage - Ground Level | 3.20833
307979 | Exist Garage - Ground Level | 7.10417
7 x 307979 | Exist Garage - Ground Level | 7.25
6 x 307979 | Exist Garage - Ground Level | 2.75
2 x 307979 | Existing Garage - Roof Level | 1.91667
2 x 307979 | Existing Garage - Roof Level | 2.47917
307979 | Existing Garage - Roof Level | 3.20833
307979 | Existing Garage - Roof Level | 2.83333

# IfcMember: Curtain Wall:(Existing) Curtainwall - Blank:307981 (259)
Classification: B2020200 Curtain Walls (Uniformat); Material: Metal - Aluminum
Pset_MemberCommon - LoadBearing: yes; IsExternal: yes; Reference: Rectangular Mullion:Curtainwall-0-Center-2 1/2" x 6"
Name (Curtain Wall:(Existing) Curtainwall - Blank:...) | In | Span (ft)
40 x 307981 | Exist Garage - Ground Level | 2.26042
6 x 307981 | Exist Garage - Ground Level | 2.35417
7 x 307981 | Exist Garage - Ground Level | 5.10417
27 x 307981 | Exist Garage - Ground Level | 2.25
26 x 307981 | Exist Garage - Ground Level | 5
24 x 307981 | Exist Garage - Ground Level | 2.75
2 x 307981 | Exist Garage - Ground Level | 2.95833
26 x 307981 | Exist Garage - Ground Level | 2.36458
6 x 307981 | Existing Garage - 1st Level | 63.8958
26 x 307981 | Exist Garage - Ground Level | 3.79167
31 x 307981 | Exist Garage - Ground Level | 2.375
19 x 307981 | Exist Garage - Ground Level | 3
2 x 307981 | Exist Garage - Ground Level | 2.39583
2 x 307981 | Existing Garage - Roof Level | 1.91667
307981 | Existing Garage - Roof Level | 1
6 x 307981 | Existing Garage - Roof Level | 2.375
3 x 307981 | Existing Garage - Roof Level | 3
2 x 307981 | Existing Garage - Roof Level | 2.9375
2 x 307981 | Existing Garage - Roof Level | 3.64583
307981 | Existing Garage - Roof Level | 0.456048

# IfcOpeningElement: Opening (220)
Name | In | Height (ft) | Width (ft) | Classification
Overhead-Rolling:8' x 10'-0":1360046:1 | Exist Garage - Ground Level | 10 | 8 | BaseQuantities - Depth: 0.96875 ft
Overhead-Rolling:8' x 10'-0":1359950:1 | Exist Garage - Ground Level | 10 | 8 | BaseQuantities - Depth: 0.96875 ft
4 x Basic Wall:(existing)Exterior - Brick on Conc - 1'-2":1208614 | Exist Garage - Ground Level | 8.44303 | 14.6667 | B2010154 Ext. Wall - Brick Cavity (Uniformat)
2 x Basic Wall:(existing)Exterior - Brick on Conc - 1'-2":1208614 | Exist Garage - Ground Level | 8.44303 | 4.75094 | B2010154 Ext. Wall - Brick Cavity (Uniformat)
Basic Wall:Exterior - Below Grade Conc 15":1284296 | Exist Garage - Ground Level |  |  | B2010140 Ext. Wall - CMU (Uniformat) | BaseQuantities - Area: 2.04362 ft2
Basic Wall:Exterior - Below Grade Conc 15":1284296 | Exist Garage - Ground Level |  |  | B2010140 Ext. Wall - CMU (Uniformat) | BaseQuantities - Area: 75.3563 ft2
Basic Wall:Exterior - Below Grade Conc 15":1284296 | Exist Garage - Ground Level | 16 | 0.5 | B2010140 Ext. Wall - CMU (Uniformat)
Basic Wall:Exterior - Below Grade Conc 15":1284296 | Exist Garage - Ground Level |  |  | B2010140 Ext. Wall - CMU (Uniformat) | BaseQuantities - Area: 4.31917 ft2
Basic Wall:(existing)Exterior - Brick on Conc - 1'-2":1208614 | Exist Garage - Ground Level | 4.75094 | 11.825 | B2010154 Ext. Wall - Brick Cavity (Uniformat)
Basic Wall:(existing)Exterior - Brick on Conc - 1'-2":1208614 | Exist Garage - Ground Level | 4.75094 | 8.22667 | B2010154 Ext. Wall - Brick Cavity (Uniformat)
Basic Wall:(existing)Exterior - Brick on Conc - 1'-2":1208614 | Exist Garage - Ground Level | 8.00667 | 14.6667 | B2010154 Ext. Wall - Brick Cavity (Uniformat)
Basic Wall:(existing)Exterior - Brick on Conc - 1'-2":1208614 | Exist Garage - Ground Level | 7.56667 | 14.6667 | B2010154 Ext. Wall - Brick Cavity (Uniformat)
Basic Wall:(existing)Exterior - Brick on Conc - 1'-2":1208614 | Exist Garage - Ground Level | 7.11667 | 14.6667 | B2010154 Ext. Wall - Brick Cavity (Uniformat)
Basic Wall:(existing)Exterior - Brick on Conc - 1'-2":1208614 | Exist Garage - Ground Level | 6.66667 | 14.6667 | B2010154 Ext. Wall - Brick Cavity (Uniformat)
Basic Wall:(existing)Exterior - Brick on Conc - 1'-2":1208614 | Exist Garage - Ground Level |  |  | B2010154 Ext. Wall - Brick Cavity (Uniformat) | BaseQuantities - Area: 18.975 ft2
Basic Wall:(existing)Exterior - Brick on Conc - 1'-2":1208614 | Exist Garage - Ground Level |  |  | B2010154 Ext. Wall - Brick Cavity (Uniformat) | BaseQuantities - Area: 13.4444 ft2
Basic Wall:(existing)Exterior - Brick on Conc - 1'-2":1208614 | Exist Garage - Ground Level |  |  | B2010154 Ext. Wall - Brick Cavity (Uniformat) | BaseQuantities - Area: 0.236111 ft2
HM_Frame_Door_-_Interior_Single_3897:3'-0" x 7'-0" Metal_5.75" x 4":1333963:1 | Exist Garage - Ground Level | 3.33333 | 7.33333 | BaseQuantities - Depth: 0.96875 ft
Exterior Double Flush:6'-0" x 7'-0" Metal_5.75" x 4":1334142:1 | Exist Garage - Ground Level | 6.33333 | 7.33333 | BaseQuantities - Depth: 0.96875 ft
Exterior Double Flush:6'-0" x 7'-0" Metal_5.75" x 4":1334051:1 | Exist Garage - Ground Level | 6.33333 | 7.33333 | BaseQuantities - Depth: 0.96875 ft
HM_Frame_Door_-_Interior_Single_3897:3'-0" x 7'-0" Metal_5.75" x 4":1333612:1 | Exist Garage - Ground Level | 3.33333 | 7.33333 | BaseQuantities - Depth: 0.96875 ft
2 x Basic Wall:(Existing) Exterior - Brick Veneer 3 5/8":519199 | Existing Garage - 1st Level | 9.11 | 4.75 | B2010158 Ext. Wall - Brick Veneer w/ Stud (Uniformat)
Basic Wall:(Existing) Exterior - Brick Veneer 3 5/8":519199 | Existing Garage - 1st Level | 8.66 | 11.6667 | B2010158 Ext. Wall - Brick Veneer w/ Stud (Uniformat)
Basic Wall:(Existing) Exterior - Brick Veneer 3 5/8":519199 | Existing Garage - 1st Level | 8.44 | 14.6667 | B2010158 Ext. Wall - Brick Veneer w/ Stud (Uniformat)
Basic Wall:(Existing) Exterior - Brick Veneer 3 5/8":519199 | Existing Garage - 1st Level | 7.99 | 14.6667 | B2010158 Ext. Wall - Brick Veneer w/ Stud (Uniformat)
Basic Wall:(Existing) Exterior - Brick Veneer 3 5/8":519199 | Existing Garage - 1st Level | 7.54 | 14.6667 | B2010158 Ext. Wall - Brick Veneer w/ Stud (Uniformat)
Basic Wall:(Existing) Exterior - Brick Veneer 3 5/8":519199 | Existing Garage - 1st Level | 7.1 | 14.6667 | B2010158 Ext. Wall - Brick Veneer w/ Stud (Uniformat)
2 x Basic Wall:(Existing) Exterior - Brick Veneer 3 5/8":519199 | Existing Garage - 1st Level | 6.88 | 4.75094 | B2010158 Ext. Wall - Brick Veneer w/ Stud (Uniformat)
2 x Basic Wall:(Existing) Exterior - Brick Veneer 3 5/8":519199 | Existing Garage - 1st Level | 9.11 | 6.41667 | B2010158 Ext. Wall - Brick Veneer w/ Stud (Uniformat)
2 x Basic Wall:(Existing) Exterior - Brick Veneer 3 5/8":519199 | Existing Garage - 1st Level | 6.41667 | 9.11 | B2010158 Ext. Wall - Brick Veneer w/ Stud (Uniformat)
2 x Basic Wall:(Existing) Exterior - Brick Veneer 3 5/8":519199 | Existing Garage - 1st Level | 4.75094 | 6.87667 | B2010158 Ext. Wall - Brick Veneer w/ Stud (Uniformat)
Basic Wall:(Existing) Exterior - Brick Veneer 3 5/8":519199 | Existing Garage - 1st Level | 14.6667 | 7.1 | B2010158 Ext. Wall - Brick Veneer w/ Stud (Uniformat)
Basic Wall:(Existing) Exterior - Brick Veneer 3 5/8":519199 | Existing Garage - 1st Level | 14.6667 | 7.54 | B2010158 Ext. Wall - Brick Veneer w/ Stud (Uniformat)
Basic Wall:(Existing) Exterior - Brick Veneer 3 5/8":519199 | Existing Garage - 1st Level | 14.6667 | 7.98667 | B2010158 Ext. Wall - Brick Veneer w/ Stud (Uniformat)
Basic Wall:(Existing) Exterior - Brick Veneer 3 5/8":519199 | Existing Garage - 1st Level | 14.6667 | 8.44 | B2010158 Ext. Wall - Brick Veneer w/ Stud (Uniformat)
Basic Wall:(Existing) Exterior - Brick Veneer 3 5/8":519199 | Existing Garage - 1st Level | 11.6667 | 8.65667 | B2010158 Ext. Wall - Brick Veneer w/ Stud (Uniformat)
Basic Wall:(Existing) Exterior - Brick Veneer 3 5/8":519199 | Existing Garage - 1st Level | 4.75 | 9.10667 | B2010158 Ext. Wall - Brick Veneer w/ Stud (Uniformat)
Basic Wall:(Existing) Exterior - Brick Veneer 3 5/8":519199 | Existing Garage - 1st Level | 4.75 | 9.11 | B2010158 Ext. Wall - Brick Veneer w/ Stud (Uniformat)
4 x Basic Wall:(Existing) Exterior - Brick Veneer 3 5/8":519199 | Existing Garage - 1st Level | 15 | 9.11 | B2010158 Ext. Wall - Brick Veneer w/ Stud (Uniformat)
Basic Wall:(Existing) Exterior - Brick Veneer 3 5/8":519199 | Existing Garage - 1st Level | 9.11 | 15 | B2010158 Ext. Wall - Brick Veneer w/ Stud (Uniformat)
Basic Wall:(Existing) Exterior - Brick Veneer 3 5/8":519199 | Existing Garage - 1st Level | 9.11 | 14.8021 | B2010158 Ext. Wall - Brick Veneer w/ Stud (Uniformat)
Basic Wall:(Existing) Exterior - Brick Veneer 3 5/8":519199 | Existing Garage - 2nd Level | 4.75 | 6.17 | B2010158 Ext. Wall - Brick Veneer w/ Stud (Uniformat)
7 x Basic Wall:(Existing) Exterior - Brick Veneer 3 5/8":519199 | Existing Garage - 2nd Level | 4.75 | 6.67 | B2010158 Ext. Wall - Brick Veneer w/ Stud (Uniformat)
4 x Basic Wall:(Existing) Exterior - Brick Veneer 3 5/8":519199 | Existing Garage - 2nd Level | 11.6667 | 6.67 | B2010158 Ext. Wall - Brick Veneer w/ Stud (Uniformat)
16 x Basic Wall:(Existing) Exterior - Brick Veneer 3 5/8":519199 | Existing Garage - 2nd Level | 14.6667 | 6.67 | B2010158 Ext. Wall - Brick Veneer w/ Stud (Uniformat)
Basic Wall:(Existing) Exterior - Brick Veneer 3 5/8":519199 | Existing Garage - 2nd Level | 4.75094 | 6.17 | B2010158 Ext. Wall - Brick Veneer w/ Stud (Uniformat)
3 x Basic Wall:(Existing) Exterior - Brick Veneer 3 5/8":519199 | Existing Garage - 2nd Level | 6.67 | 4.75094 | B2010158 Ext. Wall - Brick Veneer w/ Stud (Uniformat)
2 x Basic Wall:(Existing) Exterior - Brick Veneer 3 5/8":519199 | Existing Garage - 2nd Level | 4.75094 | 6.67 | B2010158 Ext. Wall - Brick Veneer w/ Stud (Uniformat)
Basic Wall:(Existing) Exterior - Brick Veneer 3 5/8":519199 | Existing Garage - 2nd Level | 4.75094 | 6.45 | B2010158 Ext. Wall - Brick Veneer w/ Stud (Uniformat)
Basic Wall:(Existing) Exterior - Brick Veneer 3 5/8":519199 | Existing Garage - 2nd Level | 6.45 | 4.75094 | B2010158 Ext. Wall - Brick Veneer w/ Stud (Uniformat)
16 x Basic Wall:(Existing) Exterior - Brick Veneer 3 5/8":519199 | Existing Garage - 2nd Level | 6.41667 | 6.66667 | B2010158 Ext. Wall - Brick Veneer w/ Stud (Uniformat)
32 x Basic Wall:(Existing) Exterior - Brick Veneer 3 5/8":519199 | Existing Garage - 2nd Level | 15 | 6.66667 | B2010158 Ext. Wall - Brick Veneer w/ Stud (Uniformat)
8 x Basic Wall:(Existing) Exterior - Brick Veneer 3 5/8":519199 | Existing Garage - 2nd Level | 6.66667 | 15 | B2010158 Ext. Wall - Brick Veneer w/ Stud (Uniformat)
5 x Basic Wall:(Existing) Exterior - Brick Veneer 3 5/8":519199 | Existing Garage - 2nd Level | 6.66667 | 4.75 | B2010158 Ext. Wall - Brick Veneer w/ Stud (Uniformat)
2 x Basic Wall:(Existing) Exterior - Brick Veneer 3 5/8":519199 | Existing Garage - 2nd Level | 6.66667 | 11.6667 | B2010158 Ext. Wall - Brick Veneer w/ Stud (Uniformat)
9 x Basic Wall:(Existing) Exterior - Brick Veneer 3 5/8":519199 | Existing Garage - 2nd Level | 14.6667 | 6.66667 | B2010158 Ext. Wall - Brick Veneer w/ Stud (Uniformat)
7 x Basic Wall:(Existing) Exterior - Brick Veneer 3 5/8":519199 | Existing Garage - 2nd Level | 6.66667 | 14.6667 | B2010158 Ext. Wall - Brick Veneer w/ Stud (Uniformat)
4 x Basic Wall:(Existing) Exterior - Brick Veneer 3 5/8":519199 | Existing Garage - 2nd Level | 6.66667 | 4.75094 | B2010158 Ext. Wall - Brick Veneer w/ Stud (Uniformat)
4 x Basic Wall:(Existing) Exterior - Brick Veneer 3 5/8":519199 | Existing Garage - 2nd Level | 4.75094 | 6.66667 | B2010158 Ext. Wall - Brick Veneer w/ Stud (Uniformat)
3 x Basic Wall:(Existing) Exterior - Brick Veneer 3 5/8":519199 | Existing Garage - 2nd Level | 4.75 | 6.66667 | B2010158 Ext. Wall - Brick Veneer w/ Stud (Uniformat)
2 x Basic Wall:(Existing) Exterior - Brick Veneer 3 5/8":519199 | Existing Garage - 2nd Level | 11.6667 | 6.66667 | B2010158 Ext. Wall - Brick Veneer w/ Stud (Uniformat)
HM_Frame_Door_-_Interior_Single_3897:3'-0" x 7'-0" Metal_5.75" x 4":1333663:1 | Exist Garage - Ground Level | 3.33333 | 7.33333 | BaseQuantities - Depth: 0.96875 ft
Exterior Double Flush:6'-0" x 7'-0" Metal_5.75" x 4":1334168:1 | Exist Garage - Ground Level | 6.33333 | 7.33333 | BaseQuantities - Depth: 0.96875 ft
Fixed:5'0" x 6'0":1242298:1 | Exist Garage - Ground Level | 5 | 6 | BaseQuantities - Depth: 1.25 ft
Fixed:5'0" x 6'0":1242297:1 | Exist Garage - Ground Level | 5 | 6 | BaseQuantities - Depth: 1.25 ft
Fixed:5'0" x 6'0":1242296:1 | Exist Garage - Ground Level | 5 | 6 | BaseQuantities - Depth: 1.25 ft
Fixed:6'4" x 6'0":1242295:1 | Exist Garage - Ground Level | 6.33333 | 6 | BaseQuantities - Depth: 1.25 ft
Fixed:5'0" x 6'0":1242280:1 | Exist Garage - Ground Level | 5 | 6 | BaseQuantities - Depth: 1.25 ft
Fixed:5'0" x 6'0":1242279:1 | Exist Garage - Ground Level | 5 | 6 | BaseQuantities - Depth: 1.25 ft
Fixed:5'0" x 6'0":1242278:1 | Exist Garage - Ground Level | 5 | 6 | BaseQuantities - Depth: 1.25 ft
Fixed:6'4" x 6'0":1242277:1 | Exist Garage - Ground Level | 6.33333 | 6 | BaseQuantities - Depth: 1.25 ft
Fixed:5'0" x 6'0":1242260:1 | Exist Garage - Ground Level | 5 | 6 | BaseQuantities - Depth: 1.25 ft
Fixed:5'0" x 6'0":1242259:1 | Exist Garage - Ground Level | 5 | 6 | BaseQuantities - Depth: 1.25 ft
Fixed:5'0" x 6'0":1242258:1 | Exist Garage - Ground Level | 5 | 6 | BaseQuantities - Depth: 1.25 ft
Fixed:6'4" x 6'0":1242257:1 | Exist Garage - Ground Level | 6.33333 | 6 | BaseQuantities - Depth: 1.25 ft
Fixed:5'0" x 6'0":1242240:1 | Exist Garage - Ground Level | 5 | 6 | BaseQuantities - Depth: 1.25 ft
Fixed:5'0" x 6'0":1242239:1 | Exist Garage - Ground Level | 5 | 6 | BaseQuantities - Depth: 1.25 ft
Fixed:5'0" x 6'0":1242238:1 | Exist Garage - Ground Level | 5 | 6 | BaseQuantities - Depth: 1.25 ft
Fixed:6'4" x 6'0":1242237:1 | Exist Garage - Ground Level | 6.33333 | 6 | BaseQuantities - Depth: 1.25 ft
Basic Wall:Interior - (C12) 12" cmu:1357227 | Exist Garage - Ground Level | 9 | 20.3333 | C1010120 Partitions - CMU (Uniformat) | BaseQuantities - Depth: 10 ft
Basic Wall:Interior - (C12) 12" cmu:1357227 | Exist Garage - Ground Level | 6 | 4 | C1010120 Partitions - CMU (Uniformat) | BaseQuantities - Depth: 10 ft
Basic Wall:Interior - (C12) 12" cmu:1358246 | Exist Garage - Ground Level | 20.3333 | 9 | C1010120 Partitions - CMU (Uniformat) | BaseQuantities - Depth: 10 ft
Basic Wall:Interior - (C12) 12" cmu:1358246 | Exist Garage - Ground Level | 4 | 6 | C1010120 Partitions - CMU (Uniformat) | BaseQuantities - Depth: 10 ft
Fixed:5'0" x 6'0":1242213:1 | Exist Garage - Ground Level | 5 | 6 | BaseQuantities - Depth: 1.25 ft
Fixed:5'0" x 6'0":1242212:1 | Exist Garage - Ground Level | 5 | 6 | BaseQuantities - Depth: 1.25 ft
Fixed:5'0" x 6'0":1242211:1 | Exist Garage - Ground Level | 5 | 6 | BaseQuantities - Depth: 1.25 ft
Fixed:6'4" x 6'0":1242210:1 | Exist Garage - Ground Level | 6.33333 | 6 | BaseQuantities - Depth: 1.25 ft
Fixed:5'0" x 6'0":1242085:1 | Exist Garage - Ground Level | 5 | 6 | BaseQuantities - Depth: 1.25 ft
Fixed:5'0" x 6'0":1242084:1 | Exist Garage - Ground Level | 5 | 6 | BaseQuantities - Depth: 1.25 ft
Fixed:5'0" x 6'0":1242083:1 | Exist Garage - Ground Level | 5 | 6 | BaseQuantities - Depth: 1.25 ft
Fixed:6'4" x 6'0":1242082:1 | Exist Garage - Ground Level | 6.33333 | 6 | BaseQuantities - Depth: 1.25 ft
Fixed:5'0" x 8'0":1242019:1 | Exist Garage - Ground Level | 5 | 8 | BaseQuantities - Depth: 1.25 ft
Fixed:5'0" x 8'0":1242000:1 | Exist Garage - Ground Level | 5 | 8 | BaseQuantities - Depth: 1.25 ft
Fixed:5'0" x 8'0":1241842:1 | Exist Garage - Ground Level | 5 | 8 | BaseQuantities - Depth: 1.25 ft
Fixed:6'4" x 8'0":1241742:1 | Exist Garage - Ground Level | 6.33333 | 8 | BaseQuantities - Depth: 1.25 ft
Basic Wall:Exterior - Below Grade Conc 12":360494 | Exist Garage - Ground Level |  |  | B2010140 Ext. Wall - CMU (Uniformat) | BaseQuantities - Area: 0.0123698 ft2
Basic Wall:Exterior - Below Grade Conc 12":360494 | Exist Garage - Ground Level |  |  | B2010140 Ext. Wall - CMU (Uniformat) | BaseQuantities - Area: 0.666667 ft2
Basic Wall:(existing) Exterior - Below Grade Conc 14":1238143 | Exist Garage - Ground Level |  |  | B2010140 Ext. Wall - CMU (Uniformat) | BaseQuantities - Area: 2.19361 ft2
Basic Wall:Exterior - Conc 8":1394256 | Exist Garage - Ground Level | 2.70833 | 3.41667 | B2010140 Ext. Wall - CMU (Uniformat)
Basic Wall:Exterior - Below Grade Conc 15":1284296 | Ground Floor |  |  | B2010140 Ext. Wall - CMU (Uniformat) | BaseQuantities - Area: 2.15958 ft2

# IfcPlate: 1" Insulated Clear Glass (85)
Type - ElementType: 1" Insulated Clear Glass; PredefinedType: CURTAIN_PANEL; Material: Glazing - Core & Shell Curtain Wall
Classification: B2020200 Curtain Walls (Uniformat)
Pset_PlateCommon - LoadBearing: yes; IsExternal: yes; Reference: System Panel:1" Insulated Clear Glass
Name (System Panel:1" Insulated Clear Glass:...) | In
1227237 | Exist Garage - Ground Level
1227275 | Exist Garage - Ground Level
1509219 | Exist Garage - Ground Level
1509725 | Exist Garage - Ground Level
1509726 | Exist Garage - Ground Level
1508733 | Exist Garage - Ground Level
1509221 | Exist Garage - Ground Level
1509415 | Exist Garage - Ground Level
1509321 | Exist Garage - Ground Level
1508900 | Exist Garage - Ground Level
1509224 | Exist Garage - Ground Level
1509418 | Exist Garage - Ground Level
1509324 | Exist Garage - Ground Level
1509063 | Exist Garage - Ground Level
1509227 | Exist Garage - Ground Level
1509421 | Exist Garage - Ground Level
1509327 | Exist Garage - Ground Level
1509088 | Exist Garage - Ground Level
1509230 | Exist Garage - Ground Level
1509424 | Exist Garage - Ground Level
1509330 | Exist Garage - Ground Level
1509113 | Exist Garage - Ground Level
1509233 | Exist Garage - Ground Level
1509427 | Exist Garage - Ground Level
1509333 | Exist Garage - Ground Level
1509138 | Exist Garage - Ground Level
1509236 | Exist Garage - Ground Level
1509430 | Exist Garage - Ground Level
1509336 | Exist Garage - Ground Level
1227324 | Exist Garage - Ground Level
1228685 | Exist Garage - Ground Level
1243573 | Existing Garage - 1st Level
1244524 | Existing Garage - 1st Level
1244505 | Existing Garage - 1st Level
1244760 | Existing Garage - 1st Level
1243776 | Existing Garage - 1st Level
1243739 | Existing Garage - 1st Level
1244971 | Existing Garage - 1st Level
1245001 | Existing Garage - 1st Level
1245026 | Existing Garage - 1st Level
1250814 | Exist Garage - Ground Level
1251232 | Exist Garage - Ground Level
1251271 | Exist Garage - Ground Level
1252236 | Exist Garage - Ground Level
1254417 | Existing Garage - 1st Level
1254422 | Existing Garage - 1st Level
1254424 | Existing Garage - 1st Level
1254662 | Existing Garage - 1st Level
1359331 | Exist Garage - Ground Level
1503381 | Exist Garage - Ground Level
1503389 | Exist Garage - Ground Level
1503397 | Exist Garage - Ground Level
1503411 | Exist Garage - Ground Level
1503492 | Exist Garage - Ground Level
1503575 | Exist Garage - Ground Level
1359424 | Exist Garage - Ground Level
1503086 | Exist Garage - Ground Level
1503133 | Exist Garage - Ground Level
1503134 | Exist Garage - Ground Level
1503135 | Exist Garage - Ground Level
1503017 | Exist Garage - Ground Level
1503088 | Exist Garage - Ground Level
1503112 | Exist Garage - Ground Level
1503058 | Exist Garage - Ground Level
1503091 | Exist Garage - Ground Level
1503115 | Exist Garage - Ground Level
1503064 | Exist Garage - Ground Level
1503094 | Exist Garage - Ground Level
1503118 | Exist Garage - Ground Level
1503070 | Exist Garage - Ground Level
1503097 | Exist Garage - Ground Level
1503121 | Exist Garage - Ground Level
1503076 | Exist Garage - Ground Level
1503100 | Exist Garage - Ground Level
1503124 | Exist Garage - Ground Level
1503082 | Exist Garage - Ground Level
1503103 | Exist Garage - Ground Level
1503127 | Exist Garage - Ground Level
1359475 | Exist Garage - Ground Level
1503263 | Exist Garage - Ground Level
1503281 | Exist Garage - Ground Level
1503287 | Exist Garage - Ground Level
1503295 | Exist Garage - Ground Level
1503303 | Exist Garage - Ground Level
1503311 | Exist Garage - Ground Level

# IfcRailing: Railing:Garage Security Grille (2)
In: Exist Garage - Ground Level
Classification: C2010400 Stair Handrails/Balustrades (Uniformat)
Pset_RailingCommon - IsExternal: no; Reference: Railing:Garage Security Grille; Height: 4 ft
BaseQuantities - Length: 14.6667 ft
Name (Railing:Garage Security Grille:...)
1319965
1321278

# IfcRailing: Railing:Garage Security Grille 6'-10" High (3)
In: Exist Garage - Ground Level
Classification: C2010400 Stair Handrails/Balustrades (Uniformat)
Pset_RailingCommon - IsExternal: no; Reference: Railing:Garage Security Grille 6'-10" High; Height: 4 ft
Name (Railing:Garage Security Grille 6'-10" High:...) | Length (ft)
1321301 | 14.6667
1321334 | 14.6667
1321352 | 4.75187
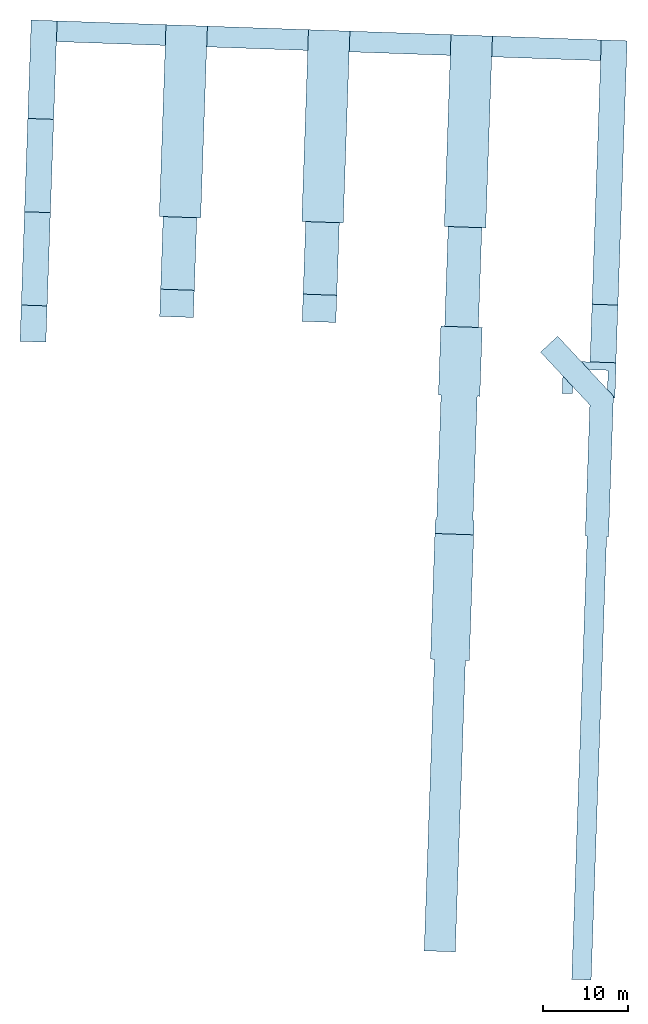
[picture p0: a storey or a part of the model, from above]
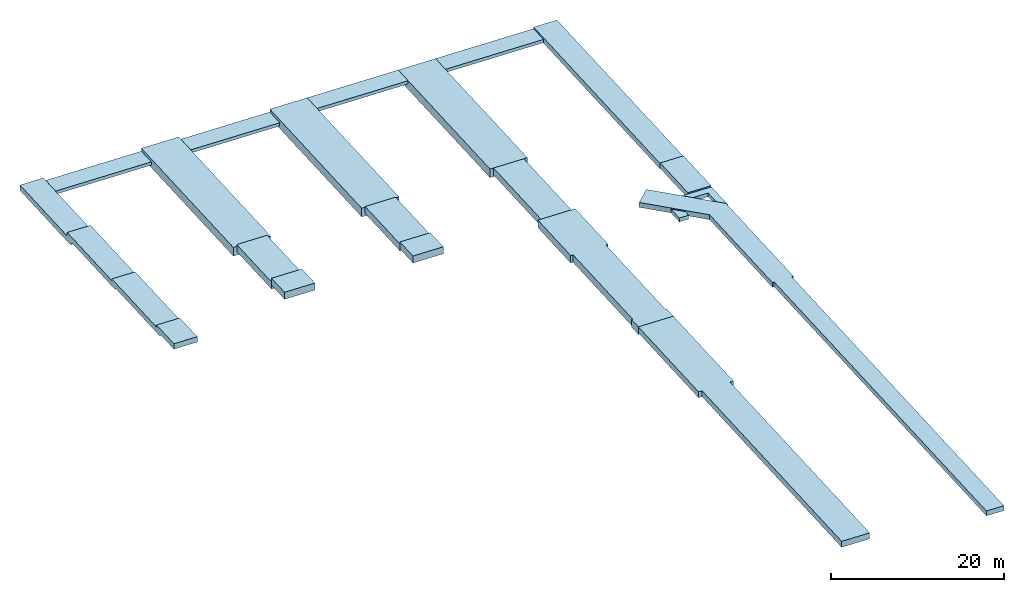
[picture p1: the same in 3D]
Properties of the parts of a building model (IFC2X3), part 2 of 2

# IfcRailing: Railing:Garage Security Grille 7'-10" High, Railing:Garage Security Grille 7'-10" High:1321550
In: 1st Floor
Classification: C2010400 Stair Handrails/Balustrades (Uniformat)
Pset_RailingCommon - IsExternal: no; Reference: Railing:Garage Security Grille 7'-10" High; Height: 4 ft
BaseQuantities - Length: 11.6667 ft

# IfcRailing: Railing:Garage Security Grille 8'-4" High (12)
Classification: C2010400 Stair Handrails/Balustrades (Uniformat)
Pset_RailingCommon - IsExternal: no; Reference: Railing:Garage Security Grille 8'-4" High; Height: 4 ft
Name (Railing:Garage Security Grille 8'-4" High:...) | In | Length (ft)
1321685 | 1st Floor | 4.75094
1321859 | 1st Floor | 4.75094
1322623 | Existing Garage - 1st Level | 6.41667
1322733 | Existing Garage - 1st Level | 6.41667
1322751 | Existing Garage - 1st Level | 15
1322818 | Existing Garage - 1st Level | 15
1322838 | Existing Garage - 1st Level | 15
1322860 | Existing Garage - 1st Level | 15
1322882 | Existing Garage - 1st Level | 15
1322902 | Existing Garage - 1st Level | 15
1323124 | Existing Garage - 1st Level | 6.41667
1323142 | Existing Garage - 1st Level | 6.41667

# IfcSlab: Floor:1.5" Metal Deck, Floor:1.5" Metal Deck:1436581
In: Exhaust Structure Roof
PredefinedType: FLOOR; Classification: B1010 Floor Construction (Uniformat); Material: Metal - Deck 0.125 ft
Pset_SlabCommon - LoadBearing: yes; IsExternal: yes; PitchAngle: 0 deg; Reference: Floor:1.5" Metal Deck
BaseQuantities - GrossArea: 58.1633 ft2; GrossVolume: 7.27041 ft3; Perimeter: 30.8333 ft; Width: 0.125 ft

# IfcSlab: Floor:Concrete Slab - 10", Floor:Concrete Slab - 10":1378308
In: Exist Garage - Ground Level
PredefinedType: FLOOR; Classification: B1010 Floor Construction (Uniformat); Material: Concrete - Cast-in-Place Concrete
Pset_SlabCommon - LoadBearing: yes; IsExternal: no; Reference: Floor:Concrete Slab - 10"
BaseQuantities - Perimeter: 174.063 ft

# IfcSlab: Floor:Concrete Slab - 5" (4)
PredefinedType: FLOOR; Classification: B1010 Floor Construction (Uniformat); Material: Concrete - Cast-in-Place Concrete 0.416667 ft
Pset_SlabCommon - LoadBearing: yes; IsExternal: no; Reference: Floor:Concrete Slab - 5"; PitchAngle: 0 deg
BaseQuantities - Width: 0.416667 ft
Name (Floor:Concrete Slab - 5":...) | In | GrossArea (ft2) | GrossVolume (ft3) | Perimeter (ft)
1225119 | Existing Garage - 1st Level | 1980 | 825 | 182
1337648 | Existing Garage - 1st Level | 1620 | 675 | 166
1409944 | Exist Garage - Ground Level | 29.9767 | 12.4903 | 24.6667
1418649 | Exist Garage - Ground Level | 20 | 8.33333 | 18

# IfcSlab: Floor:Concrete Slab - 6" (4)
In: Exist Garage - Ground Level
PredefinedType: FLOOR; Classification: B1010 Floor Construction (Uniformat); Material: Concrete - Cast-in-Place Concrete 0.5 ft
Pset_SlabCommon - LoadBearing: yes; IsExternal: no; PitchAngle: 0 deg; Reference: Floor:Concrete Slab - 6"
BaseQuantities - Width: 0.5 ft
Name (Floor:Concrete Slab - 6":...) | GrossArea (ft2) | GrossVolume (ft3) | Perimeter (ft)
1273386 | 378.217 | 189.109 | 83.908
1278366 | 48.5697 | 24.2848 | 31.1478
1621268 | 188.622 | 94.311 | 60.9815
1621556 | 188.622 | 94.311 | 60.9815

# IfcSlab: Floor:Concrete Slab - 8" (2)
PredefinedType: FLOOR; Classification: B1010 Floor Construction (Uniformat); Material: Concrete - Cast-in-Place Concrete 0.666667 ft
Pset_SlabCommon - LoadBearing: yes; IsExternal: no; PitchAngle: 0 deg; Reference: Floor:Concrete Slab - 8"
BaseQuantities - GrossArea: 372 ft2; GrossVolume: 248 ft3; Perimeter: 86 ft; Width: 0.666667 ft
Name (Floor:Concrete Slab - 8":...) | In
1338195 | Existing Garage - 1st Level
1616650 | Exist Garage - Ground Level

# IfcWall: Basic Wall:(existing) Exterior - Brick on CMU - 1'-0", Basic Wall:(existing) Exterior - Brick on CMU - 1'-0":1233094
In: Exist Garage - Ground Level
Type - PredefinedType: STANDARD; Material: Masonry - Brick 0.302083 ft, Insulation / Thermal Barriers - Rigid insulation 0.0625 ft, Masonry - Concrete Masonry Units 0.635417 ft
Classification: B2010154 Ext. Wall - Brick Cavity (Uniformat)
Pset_WallCommon - LoadBearing: no; ExtendToStructure: no; IsExternal: yes; Reference: Basic Wall:(existing) Exterior - Brick on CMU - 1'-0"

# IfcWallStandardCase: Basic Wall:(Existing) Exterior - Brick Veneer 3 5/8" (59)
Type - PredefinedType: STANDARD; Material: Masonry - Brick 0.302083 ft
Classification: B2010158 Ext. Wall - Brick Veneer w/ Stud (Uniformat)
BaseQuantities - Width: 0.302083 ft
Pset_WallCommon - LoadBearing: no; ExtendToStructure: no; IsExternal: yes; Reference: Basic Wall:(Existing) Exterior - Brick Veneer 3 5/8"
Name (Basic Wall:(Existing) Exterior - Brick Veneer 3 5/8":...) | In | Height (ft) | Length (ft) | GrossFootprintArea (ft2) | GrossSideArea (ft2) | GrossVolume (ft3)
1211203 | Existing Garage - 1st Level | 10 | 120.002 | 36.2506 | 491.374 | 148.436
1211256 | Existing Garage - 1st Level | 13.28 | 21.1979 | 6.40354 | 164.597 | 49.7219
1211296 | Existing Garage - 1st Level | 10 | 121.932 | 36.8337 | 510.814 | 154.308
1213137 | Existing Garage - 1st Level | 13.28 | 131.5 | 39.724 | 811.311 | 245.084
1213248 | Existing Garage - 1st Level | 13.28 | 3.33333 | 1.00694 | 44.2667 | 13.3722
1214551 | Existing Garage - 2nd Level | 43.5 | 122.234 | 36.925 | 2940.57 | 888.298
1214685 | Existing Garage - 2nd Level | 44 | 222.698 | 67.2733 | 5114.26 | 1544.93
1214733 | Existing Garage - 2nd Level | 44 | 119.7 | 36.1593 | 2884.52 | 871.365
1226397 | Exist Garage - Ground Level | 66.25 | 1.75 | 0.528646 | 115.938 | 35.0228
1227646 | Exist Garage - Ground Level | 65.8125 | 3.66667 | 1.10764 | 241.312 | 72.8965
1227876 | Exist Garage - Ground Level | 66.25 | 2.15625 | 0.651367 | 142.852 | 43.1531
1229835 | Exist Garage - Ground Level | 65.8125 | 3.66667 | 1.10764 | 241.312 | 72.8965
1229867 | Exist Garage - Ground Level | 65.8125 | 3.66667 | 1.10764 | 241.312 | 72.8965
1230057 | Exist Garage - Ground Level | 65.8125 | 3 | 0.90625 | 197.438 | 59.6426
1232153 | Exist Garage - Ground Level | 65.8125 | 3 | 0.90625 | 197.438 | 59.6426
1232162 | Exist Garage - Ground Level | 65.8125 | 3 | 0.90625 | 197.438 | 59.6426
1232171 | Exist Garage - Ground Level | 65.8125 | 3 | 0.90625 | 197.438 | 59.6426
1232180 | Exist Garage - Ground Level | 65.8125 | 3 | 0.90625 | 197.438 | 59.6426
1232189 | Exist Garage - Ground Level | 65.8125 | 3 | 0.90625 | 197.438 | 59.6426
1232198 | Exist Garage - Ground Level | 65.8125 | 3 | 0.90625 | 197.438 | 59.6426
1232207 | Exist Garage - Ground Level | 65.8125 | 3 | 0.90625 | 197.438 | 59.6426
1232216 | Exist Garage - Ground Level | 65.8125 | 3 | 0.90625 | 197.438 | 59.6426
1232622 | Exist Garage - Ground Level | 65.8125 | 3 | 0.90625 | 197.438 | 59.6426
1232629 | Exist Garage - Ground Level | 65.8125 | 4.17344 | 1.18418 | 274.665 | 77.9341
1234874 | Exist Garage - Ground Level | 65.8125 | 2.32305 | 0.625209 | 152.885 | 41.1466
1235001 | Exist Garage - Ground Level | 65.8125 | 2.14583 | 0.64822 | 141.223 | 42.661
1235131 | Exist Garage - Ground Level | 65.8125 | 2.00321 | 0.605136 | 131.836 | 39.8255
1239252 | Existing Garage - 1st Level | 53.5625 | 3.66667 | 1.10764 | 196.396 | 59.3279
1239595 | Existing Garage - 1st Level | 53.5625 | 3.36458 | 1.01638 | 180.215 | 54.4401
1239847 | Existing Garage - 1st Level | 53.5625 | 3.66667 | 1.10764 | 196.396 | 59.3279
1245549 | Existing Garage - 1st Level | 53.5625 | 1.5 | 0.453125 | 80.3438 | 24.2705
1245577 | Existing Garage - 1st Level | 53.5625 | 2.92188 | 0.88265 | 156.503 | 47.2769
1245606 | Existing Garage - 1st Level | 53.5625 | 1.99479 | 0.602593 | 106.846 | 32.2764
1245635 | Existing Garage - 1st Level | 53.5625 | 0.963542 | 0.29107 | 51.6097 | 15.5904
1245676 | Existing Garage - 1st Level | 53.5625 | 0.796875 | 0.240723 | 42.6826 | 12.8937
1245714 | Existing Garage - 1st Level | 53.5625 | 1.65625 | 0.500326 | 88.7129 | 26.7987
1245803 | Existing Garage - 1st Level | 53.5625 | 3.66689 | 1.1077 | 196.408 | 59.3314
1246078 | Exist Garage - Ground Level | 65.8125 | 3 | 0.90625 | 197.437 | 59.6426
1246087 | Exist Garage - Ground Level | 65.8125 | 3.66667 | 1.10764 | 241.312 | 72.8965
1246096 | Exist Garage - Ground Level | 65.8125 | 3.66667 | 1.10764 | 241.313 | 72.8965
1246331 | Exist Garage - Ground Level | 65.8125 | 2.18229 | 0.659234 | 143.622 | 43.3858
1251589 | Exist Garage - Ground Level | 65.8125 | 2.33333 | 0.704861 | 153.562 | 46.3887
1251590 | Exist Garage - Ground Level | 65.8125 | 3.36458 | 1.01638 | 221.432 | 66.8908
1252826 | Exist Garage - Ground Level | 65.8125 | 2 | 0.604167 | 131.625 | 39.7617
1253159 | Exist Garage - Ground Level | 65.8125 | 3.66667 | 1.10764 | 241.313 | 72.8965
1253338 | Exist Garage - Ground Level | 65.8125 | 3.66667 | 1.10764 | 241.313 | 72.8965
1253368 | Exist Garage - Ground Level | 65.8125 | 3 | 0.90625 | 197.438 | 59.6426
1254347 | Exist Garage - Ground Level | 65.8125 | 2.33333 | 0.704861 | 153.562 | 46.3887
1254348 | Exist Garage - Ground Level | 65.8125 | 3.36458 | 1.01638 | 221.432 | 66.8908
1254961 | Exist Garage - Ground Level | 65.8125 | 2 | 0.604167 | 131.625 | 39.7617
1255022 | Exist Garage - Ground Level | 65.8125 | 3.66671 | 1.10765 | 241.315 | 72.8973
1255242 | Exist Garage - Ground Level | 65.8125 | 3.66671 | 1.10765 | 241.315 | 72.8973
1255311 | Exist Garage - Ground Level | 65.8125 | 3 | 0.90625 | 197.438 | 59.6426
1255467 | Exist Garage - Ground Level | 65.8125 | 3 | 0.90625 | 197.438 | 59.6426
1255538 | Exist Garage - Ground Level | 65.8125 | 3 | 0.90625 | 197.438 | 59.6426
1255549 | Exist Garage - Ground Level | 65.8125 | 3 | 0.90625 | 197.438 | 59.6426
1255560 | Exist Garage - Ground Level | 65.8125 | 3 | 0.90625 | 197.438 | 59.6426
1255569 | Exist Garage - Ground Level | 65.8125 | 3 | 0.90625 | 197.438 | 59.6426
1255578 | Exist Garage - Ground Level | 65.8125 | 3 | 0.90625 | 197.438 | 59.6426

# IfcWallStandardCase: Basic Wall:(existing) Exterior - Below Grade Conc 14" (5)
In: Exist Garage - Ground Level
Type - PredefinedType: STANDARD; Material: Concrete - Cast-in-Place Concrete 1.16667 ft
Classification: B2010140 Ext. Wall - CMU (Uniformat)
BaseQuantities - Width: 1.16667 ft
Pset_WallCommon - ExtendToStructure: no; IsExternal: yes; Reference: Basic Wall:(existing) Exterior - Below Grade Conc 14"
Name (Basic Wall:(existing) Exterior - Below Grade Conc 14":...) | Height (ft) | Length (ft) | GrossFootprintArea (ft2) | GrossSideArea (ft2) | GrossVolume (ft3) | LoadBearing
1237313 | 12.25 | 48.0875 | 56.102 | 590.22 | 687.25 | no
1364812 | 1.66667 | 2.33333 | 2.72222 | 3.88888 | 4.53703 | yes
1405669 | 11.9367 | 30.25 | 35.2917 | 361.084 | 421.265 | yes
1406265 | 2.02 | 80.4176 | 93.8205 | 158.056 | 184.399 | yes
1413352 | 1.66667 | 7.24906 | 8.45724 | 12.0818 | 14.0954 | yes

# IfcWallStandardCase: Basic Wall:(existing) Exterior - Brick on CMU - 1'-0" (6)
Type - PredefinedType: STANDARD; Material: Masonry - Brick 0.302083 ft, Insulation / Thermal Barriers - Rigid insulation 0.0625 ft, Masonry - Concrete Masonry Units 0.635417 ft
Classification: B2010154 Ext. Wall - Brick Cavity (Uniformat)
BaseQuantities - Width: 1 ft
Pset_WallCommon - LoadBearing: no; ExtendToStructure: no; IsExternal: yes; Reference: Basic Wall:(existing) Exterior - Brick on CMU - 1'-0"
Name (Basic Wall:(existing) Exterior - Brick on CMU - 1'-0":...) | In | Height (ft) | Length (ft) | GrossFootprintArea (ft2) | GrossSideArea (ft2) | GrossVolume (ft3)
1232960 | Exist Garage - Ground Level | 3.58008 | 1.95524 | 1.71199 | 6.9999 | 6.12907
1233016 | Exist Garage - Ground Level | 3.58008 | 6.23211 | 5.8737 | 21.4868 | 21.0283
1233400 | Exist Garage - Ground Level | 3.58008 | 1.95524 | 1.71199 | 6.9999 | 6.12907
1233401 | Exist Garage - Ground Level | 3.58008 | 6.23211 | 5.8737 | 21.4868 | 21.0283
1240126 | Existing Garage - 1st Level | 53.5625 | 2 | 2 | 107.125 | 107.125
1242400 | Exist Garage - Ground Level | 62.25 | 26.6667 | 26.6667 | 1660 | 1660

# IfcWallStandardCase: Basic Wall:(existing) Exterior - Brick on CMU - 1'-2" (15)
Type - PredefinedType: STANDARD; Material: Masonry - Brick 0.302083 ft, Air Barrier - Air Infiltration Barrier 0.229167 ft, Masonry - Concrete Masonry Units 0.635417 ft
Classification: B2010154 Ext. Wall - Brick Cavity (Uniformat)
BaseQuantities - Width: 1.16667 ft
Pset_WallCommon - LoadBearing: no; ExtendToStructure: no; IsExternal: yes; Reference: Basic Wall:(existing) Exterior - Brick on CMU - 1'-2"
Name (Basic Wall:(existing) Exterior - Brick on CMU - 1'-2":...) | In | Height (ft) | Length (ft) | GrossFootprintArea (ft2) | GrossSideArea (ft2) | GrossVolume (ft3)
1246912 | Existing Garage - 1st Level | 53.5625 | 3 | 3.5 | 160.688 | 187.469
1247115 | Exist Garage - Ground Level | 65.8125 | 3 | 3.5 | 197.438 | 230.344
1247271 | Existing Garage - 1st Level | 53.5625 | 3 | 3.5 | 160.688 | 187.469
1247610 | Existing Garage - 1st Level | 53.5625 | 2 | 2.33333 | 107.125 | 124.979
1247860 | Existing Garage - 1st Level | 53.5625 | 2 | 2.33333 | 107.125 | 124.979
1248767 | Existing Garage - 1st Level | 53.5625 | 3 | 3.5 | 160.688 | 187.469
1248768 | Exist Garage - Ground Level | 65.8125 | 3 | 3.5 | 197.438 | 230.344
1248939 | Existing Garage - 1st Level | 53.5625 | 3 | 3.5 | 160.688 | 187.469
1248940 | Existing Garage - 1st Level | 53.5625 | 2 | 2.33333 | 107.125 | 124.979
1248941 | Existing Garage - 1st Level | 53.5625 | 2 | 2.33333 | 107.125 | 124.979
1538793 | Existing Garage - 2nd Level | 5.95333 | 4.75094 | 5.54276 | 28.2839 | 32.9979
1538912 | Existing Garage - 3rd Level | 6.17333 | 4.75094 | 5.54276 | 29.3291 | 34.2173
1538932 | Existing Garage - 4th Level | 6.17333 | 4.75094 | 5.54276 | 29.3291 | 34.2173
1538952 | Existing Garage - 5th Level | 6.17333 | 4.75094 | 5.54276 | 29.3291 | 34.2173
1539774 | Existing Garage - 1st Level | 6.38333 | 4.75094 | 5.54276 | 30.3268 | 35.3813

# IfcWallStandardCase: Basic Wall:(existing)Exterior - 10" Conc (3)
In: Exist Garage - Ground Level
Type - PredefinedType: STANDARD; Material: Concrete - Cast-in-Place Concrete_hatch surface 0.833333 ft
Classification: B2010154 Ext. Wall - Brick Cavity (Uniformat)
BaseQuantities - Width: 0.833333 ft
Pset_WallCommon - LoadBearing: no; ExtendToStructure: no; IsExternal: yes; Reference: Basic Wall:(existing)Exterior - 10" Conc
Name (Basic Wall:(existing)Exterior - 10" Conc:...) | Height (ft) | Length (ft) | GrossFootprintArea (ft2) | GrossSideArea (ft2) | GrossVolume (ft3)
1237442 | 65.8125 | 3.95906 | 3.29921 | 260.555 | 217.129
1239065 | 65.8125 | 2 | 1.66667 | 131.625 | 109.688
1243307 | 62.25 | 8.16667 | 6.80556 | 508.375 | 423.646

# IfcWallStandardCase: Basic Wall:(existing)Exterior - 12" Conc (10)
In: Exist Garage - Ground Level
Type - PredefinedType: STANDARD; Material: Concrete - Cast-in-Place Concrete_hatch surface 1 ft
Classification: B2010154 Ext. Wall - Brick Cavity (Uniformat)
BaseQuantities - Width: 1 ft
Pset_WallCommon - ExtendToStructure: no; IsExternal: yes; Reference: Basic Wall:(existing)Exterior - 12" Conc
Name (Basic Wall:(existing)Exterior - 12" Conc:...) | Height (ft) | Length (ft) = GrossFootprintArea (ft2) | GrossSideArea (ft2) = GrossVolume (ft3) | LoadBearing
1273829 | 1.5 | 2.8125 | 4.21875 | no
1273932 | 2 | 4.95833 | 9.91667 | no
1274017 | 2 | 9.85417 | 19.7083 | no
1274071 | 2 | 17.4167 | 34.8333 | no
1274702 | 8 | 3.3125 | 26.5 | no
1274762 | 8 | 4.5 | 36 | no
1274808 | 8 | 9.83333 | 78.6667 | no
1274863 | 8 | 17.5 | 140 | no
1312315 | 10.8623 | 16 | 169.348 | yes
1312384 | 11.9617 | 13 | 152.552 | yes

# IfcWallStandardCase: Basic Wall:(existing)Exterior - 6" Conc (8)
In: Exist Garage - Ground Level
Type - PredefinedType: STANDARD; Material: Concrete - Cast-in-Place Concrete_hatch surface 0.5 ft
Classification: B2010154 Ext. Wall - Brick Cavity (Uniformat)
BaseQuantities - Height: 2.5 ft; Width: 0.5 ft
Pset_WallCommon - LoadBearing: no; ExtendToStructure: no; IsExternal: yes; Reference: Basic Wall:(existing)Exterior - 6" Conc
Name (Basic Wall:(existing)Exterior - 6" Conc:...) | Length (ft) | GrossFootprintArea (ft2) | GrossSideArea (ft2) | GrossVolume (ft3)
1273033 | 5.45833 | 2.72917 | 13.6458 | 6.82292
1273142 | 10.3333 | 5.16667 | 25.8333 | 12.9167
1273210 | 17.9167 | 8.95833 | 44.7917 | 22.3958
1273288 | 1.8125 | 0.90625 | 4.53125 | 2.26563
1275368 | 1.8125 | 0.90625 | 4.53125 | 2.26562
1275409 | 5 | 2.5 | 12.5 | 6.25
1275454 | 10.3333 | 5.16667 | 25.8333 | 12.9167
1275510 | 18.0008 | 9.00039 | 45.0019 | 22.501

# IfcWallStandardCase: Basic Wall:(existing)Exterior - Brick on Conc - 1'-2" (2)
In: Exist Garage - Ground Level
Type - PredefinedType: STANDARD; Material: Masonry - Brick 0.302083 ft, Misc. Air Layers - Air Space 0.03125 ft, Concrete - Cast-in-Place Concrete_hatch surface 0.833333 ft
Classification: B2010154 Ext. Wall - Brick Cavity (Uniformat)
BaseQuantities - Height: 12.25 ft; Width: 1.16667 ft
Pset_WallCommon - Reference: Basic Wall:(existing)Exterior - Brick on Conc - 1'-2"; LoadBearing: no; ExtendToStructure: no; IsExternal: yes
Name (Basic Wall:(existing)Exterior - Brick on Conc - 1'-2":...) | Length (ft) | GrossFootprintArea (ft2) | GrossSideArea (ft2) | GrossVolume (ft3)
1208555 | 120.002 | 140.002 | 894.474 | 1043.55
1208803 | 119.377 | 139.273 | 729.437 | 851.009

# IfcWallStandardCase: Basic Wall:(existing)Exterior - Brick on Conc - 1'-2"(2" air space) (130)
Type - PredefinedType: STANDARD; Material: Masonry - Brick 0.302083 ft, Misc. Air Layers - Air Space 0.197917 ft, Concrete - Cast-in-Place Concrete_hatch surface 0.666667 ft
Classification: B2010154 Ext. Wall - Brick Cavity (Uniformat)
BaseQuantities - Width: 1.16667 ft
Pset_WallCommon - LoadBearing: no; ExtendToStructure: no; IsExternal: yes; Reference: Basic Wall:(existing)Exterior - Brick on Conc - 1'-2"(2" air space)
Name (Basic Wall:(existing)Exterior - Brick on Conc - 1'-2"(2" air space):...) | In | Height (ft) | Length (ft) | GrossFootprintArea (ft2) | GrossSideArea (ft2) | GrossVolume (ft3)
1230392 | Existing Garage - 1st Level | 2.89583 | 11.3333 | 13.2222 | 32.8194 | 38.2894
1230654 | Existing Garage - 1st Level | 2.89583 | 11.3334 | 13.2223 | 32.8196 | 38.2895
1231003 | Existing Garage - 2nd Level | 2.89583 | 11.3333 | 13.2222 | 32.8194 | 38.2894
1231004 | Existing Garage - 2nd Level | 2.89583 | 11.3334 | 13.2223 | 32.8196 | 38.2895
1231014 | Existing Garage - 3rd Level | 2.89583 | 11.3333 | 13.2222 | 32.8194 | 38.2894
1231015 | Existing Garage - 3rd Level | 2.89583 | 11.3334 | 13.2223 | 32.8196 | 38.2895
1231025 | Existing Garage - 4th Level | 2.89583 | 11.3333 | 13.2222 | 32.8194 | 38.2894
1231026 | Existing Garage - 4th Level | 2.89583 | 11.3334 | 13.2223 | 32.8196 | 38.2895
1231036 | Existing Garage - 5th Level | 2.89583 | 11.3333 | 13.2222 | 32.8194 | 38.2894
1231037 | Existing Garage - 5th Level | 2.89583 | 11.3334 | 13.2223 | 32.8196 | 38.2895
1231039 | Existing Garage - Roof Level | 3.5625 | 11.3333 | 13.2222 | 40.375 | 47.1042
1231040 | Existing Garage - Roof Level | 3.5625 | 11.3334 | 13.2223 | 40.3752 | 47.1043
1231854 | Existing Garage - Roof Level | 3.5625 | 14.3333 | 16.7222 | 51.0625 | 59.5729
1240419 | Existing Garage - 1st Level | 2.89583 | 6.66667 | 7.77778 | 19.3056 | 22.5231
1240535 | Existing Garage - 1st Level | 2.89583 | 6.66667 | 7.77778 | 19.3056 | 22.5231
1240589 | Existing Garage - 2nd Level | 2.89583 | 6.66667 | 7.77778 | 19.3056 | 22.5231
1240590 | Existing Garage - 2nd Level | 2.89583 | 6.66667 | 7.77778 | 19.3056 | 22.5231
1240592 | Existing Garage - 3rd Level | 2.89583 | 6.66667 | 7.77778 | 19.3056 | 22.5231
1240593 | Existing Garage - 3rd Level | 2.89583 | 6.66667 | 7.77778 | 19.3056 | 22.5231
1240599 | Existing Garage - 4th Level | 2.89583 | 6.66667 | 7.77778 | 19.3056 | 22.5231
1240600 | Existing Garage - 4th Level | 2.89583 | 6.66667 | 7.77778 | 19.3056 | 22.5231
1240606 | Existing Garage - 5th Level | 2.89583 | 6.66667 | 7.77778 | 19.3056 | 22.5231
1240607 | Existing Garage - 5th Level | 2.89583 | 6.66667 | 7.77778 | 19.3056 | 22.5231
1240613 | Existing Garage - Roof Level | 2.89583 | 6.66667 | 7.77778 | 19.3056 | 22.5231
1240614 | Existing Garage - Roof Level | 2.89583 | 6.66667 | 7.77778 | 19.3056 | 22.5231
1247702 | Existing Garage - 1st Level | 2.89583 | 6.4167 | 7.48615 | 18.5817 | 21.6786
1248507 | Existing Garage - 1st Level | 2.89583 | 6.4167 | 7.48615 | 18.5817 | 21.6786
1248528 | Existing Garage - 1st Level | 2.89583 | 6.4167 | 7.48615 | 18.5817 | 21.6786
1248536 | Existing Garage - 1st Level | 2.89583 | 6.4167 | 7.48615 | 18.5817 | 21.6786
1248568 | Existing Garage - 2nd Level | 2.89583 | 6.4167 | 7.48615 | 18.5817 | 21.6786
1248569 | Existing Garage - 2nd Level | 2.89583 | 6.4167 | 7.48615 | 18.5817 | 21.6786
1248570 | Existing Garage - 2nd Level | 2.89583 | 6.4167 | 7.48615 | 18.5817 | 21.6786
1248571 | Existing Garage - 2nd Level | 2.89583 | 6.4167 | 7.48615 | 18.5817 | 21.6786
1248577 | Existing Garage - 3rd Level | 2.89583 | 6.4167 | 7.48615 | 18.5817 | 21.6786
1248578 | Existing Garage - 3rd Level | 2.89583 | 6.4167 | 7.48615 | 18.5817 | 21.6786
1248579 | Existing Garage - 3rd Level | 2.89583 | 6.4167 | 7.48615 | 18.5817 | 21.6786
1248580 | Existing Garage - 3rd Level | 2.89583 | 6.4167 | 7.48615 | 18.5817 | 21.6786
1248586 | Existing Garage - 4th Level | 2.89583 | 6.4167 | 7.48615 | 18.5817 | 21.6786
1248587 | Existing Garage - 4th Level | 2.89583 | 6.4167 | 7.48615 | 18.5817 | 21.6786
1248588 | Existing Garage - 4th Level | 2.89583 | 6.4167 | 7.48615 | 18.5817 | 21.6786
1248589 | Existing Garage - 4th Level | 2.89583 | 6.4167 | 7.48615 | 18.5817 | 21.6786
1248595 | Existing Garage - 5th Level | 2.89583 | 6.4167 | 7.48615 | 18.5817 | 21.6786
1248596 | Existing Garage - 5th Level | 2.89583 | 6.4167 | 7.48615 | 18.5817 | 21.6786
1248597 | Existing Garage - 5th Level | 2.89583 | 6.4167 | 7.48615 | 18.5817 | 21.6786
1248598 | Existing Garage - 5th Level | 2.89583 | 6.4167 | 7.48615 | 18.5817 | 21.6786
1248604 | Existing Garage - Roof Level | 2.89583 | 6.4167 | 7.48615 | 18.5817 | 21.6786
1248605 | Existing Garage - Roof Level | 2.89583 | 6.4167 | 7.48615 | 18.5817 | 21.6786
1248606 | Existing Garage - Roof Level | 2.89583 | 6.4167 | 7.48615 | 18.5817 | 21.6786
1248607 | Existing Garage - Roof Level | 2.89583 | 6.4167 | 7.48615 | 18.5817 | 21.6786
1248636 | Existing Garage - 1st Level | 2.89583 | 15.3333 | 17.8889 | 44.4028 | 51.8032
1248693 | Existing Garage - 1st Level | 2.89583 | 15.3333 | 17.8889 | 44.4028 | 51.8032
1248701 | Existing Garage - 1st Level | 2.89583 | 15.3333 | 17.8889 | 44.4028 | 51.8032
1248734 | Existing Garage - 2nd Level | 2.89583 | 15.3333 | 17.8889 | 44.4028 | 51.8032
1248735 | Existing Garage - 2nd Level | 2.89583 | 15.3333 | 17.8889 | 44.4028 | 51.8032
1248736 | Existing Garage - 2nd Level | 2.89583 | 15.3333 | 17.8889 | 44.4028 | 51.8032
1248742 | Existing Garage - 3rd Level | 2.89583 | 15.3333 | 17.8889 | 44.4028 | 51.8032
1248743 | Existing Garage - 3rd Level | 2.89583 | 15.3333 | 17.8889 | 44.4028 | 51.8032
1248744 | Existing Garage - 3rd Level | 2.89583 | 15.3333 | 17.8889 | 44.4028 | 51.8032
1248746 | Existing Garage - 4th Level | 2.89583 | 15.3333 | 17.8889 | 44.4028 | 51.8032
1248747 | Existing Garage - 4th Level | 2.89583 | 15.3333 | 17.8889 | 44.4028 | 51.8032
1248748 | Existing Garage - 4th Level | 2.89583 | 15.3333 | 17.8889 | 44.4028 | 51.8032
1248750 | Existing Garage - 5th Level | 2.89583 | 15.3333 | 17.8889 | 44.4028 | 51.8032
1248751 | Existing Garage - 5th Level | 2.89583 | 15.3333 | 17.8889 | 44.4028 | 51.8032
1248752 | Existing Garage - 5th Level | 2.89583 | 15.3333 | 17.8889 | 44.4028 | 51.8032
1248754 | Existing Garage - Roof Level | 2.89583 | 15.3333 | 17.8889 | 44.4028 | 51.8032
1248755 | Existing Garage - Roof Level | 2.89583 | 15.3333 | 17.8889 | 44.4028 | 51.8032
1248756 | Existing Garage - Roof Level | 2.89583 | 15.3333 | 17.8889 | 44.4028 | 51.8032
1248794 | Existing Garage - 1st Level | 2.89583 | 15.3331 | 17.8886 | 44.4021 | 51.8025
1248802 | Existing Garage - 1st Level | 2.89583 | 15.3333 | 17.8889 | 44.4028 | 51.8032
1248810 | Existing Garage - 1st Level | 2.89583 | 15.3333 | 17.8889 | 44.4028 | 51.8032
1248831 | Existing Garage - 2nd Level | 2.89583 | 15.3331 | 17.8886 | 44.4021 | 51.8025
1248832 | Existing Garage - 2nd Level | 2.89583 | 15.3333 | 17.8889 | 44.4028 | 51.8032
1248833 | Existing Garage - 2nd Level | 2.89583 | 15.3333 | 17.8889 | 44.4028 | 51.8032
1248835 | Existing Garage - 3rd Level | 2.89583 | 15.3331 | 17.8886 | 44.4021 | 51.8025
1248836 | Existing Garage - 3rd Level | 2.89583 | 15.3333 | 17.8889 | 44.4028 | 51.8032
1248837 | Existing Garage - 3rd Level | 2.89583 | 15.3333 | 17.8889 | 44.4028 | 51.8032
1248843 | Existing Garage - 4th Level | 2.89583 | 15.3331 | 17.8886 | 44.4021 | 51.8025
1248844 | Existing Garage - 4th Level | 2.89583 | 15.3333 | 17.8889 | 44.4028 | 51.8032
1248845 | Existing Garage - 4th Level | 2.89583 | 15.3333 | 17.8889 | 44.4028 | 51.8032
1248847 | Existing Garage - 5th Level | 2.89583 | 15.3331 | 17.8886 | 44.4021 | 51.8025
1248848 | Existing Garage - 5th Level | 2.89583 | 15.3333 | 17.8889 | 44.4028 | 51.8032
1248849 | Existing Garage - 5th Level | 2.89583 | 15.3333 | 17.8889 | 44.4028 | 51.8032
1248851 | Existing Garage - Roof Level | 2.89583 | 15.3331 | 17.8886 | 44.4021 | 51.8025
1248852 | Existing Garage - Roof Level | 2.89583 | 15.3333 | 17.8889 | 44.4028 | 51.8032
1248853 | Existing Garage - Roof Level | 2.89583 | 15.3333 | 17.8889 | 44.4028 | 51.8032
1248959 | Existing Garage - 1st Level | 2.89583 | 6.41667 | 7.48611 | 18.5816 | 21.6785
1249362 | Existing Garage - 1st Level | 2.89583 | 6.41667 | 7.48611 | 18.5816 | 21.6785
1249372 | Existing Garage - 1st Level | 2.89583 | 6.41667 | 7.48611 | 18.5816 | 21.6785
1249380 | Existing Garage - 1st Level | 2.89583 | 6.41667 | 7.48611 | 18.5816 | 21.6785
1250534 | Existing Garage - 2nd Level | 2.89583 | 6.41667 | 7.48611 | 18.5816 | 21.6785
1250535 | Existing Garage - 2nd Level | 2.89583 | 6.41667 | 7.48611 | 18.5816 | 21.6785
1250536 | Existing Garage - 2nd Level | 2.89583 | 6.41667 | 7.48611 | 18.5816 | 21.6785
1250537 | Existing Garage - 2nd Level | 2.89583 | 6.41667 | 7.48611 | 18.5816 | 21.6785
1250539 | Existing Garage - 3rd Level | 2.89583 | 6.41667 | 7.48611 | 18.5816 | 21.6785
1250540 | Existing Garage - 3rd Level | 2.89583 | 6.41667 | 7.48611 | 18.5816 | 21.6785
1250541 | Existing Garage - 3rd Level | 2.89583 | 6.41667 | 7.48611 | 18.5816 | 21.6785
1250542 | Existing Garage - 3rd Level | 2.89583 | 6.41667 | 7.48611 | 18.5816 | 21.6785
1250544 | Existing Garage - 4th Level | 2.89583 | 6.41667 | 7.48611 | 18.5816 | 21.6785
1250545 | Existing Garage - 4th Level | 2.89583 | 6.41667 | 7.48611 | 18.5816 | 21.6785
1250546 | Existing Garage - 4th Level | 2.89583 | 6.41667 | 7.48611 | 18.5816 | 21.6785
1250547 | Existing Garage - 4th Level | 2.89583 | 6.41667 | 7.48611 | 18.5816 | 21.6785
1250549 | Existing Garage - 5th Level | 2.89583 | 6.41667 | 7.48611 | 18.5816 | 21.6785
1250550 | Existing Garage - 5th Level | 2.89583 | 6.41667 | 7.48611 | 18.5816 | 21.6785
1250551 | Existing Garage - 5th Level | 2.89583 | 6.41667 | 7.48611 | 18.5816 | 21.6785
1250552 | Existing Garage - 5th Level | 2.89583 | 6.41667 | 7.48611 | 18.5816 | 21.6785
1250554 | Existing Garage - Roof Level | 2.89583 | 6.41667 | 7.48611 | 18.5816 | 21.6785
1250555 | Existing Garage - Roof Level | 2.89583 | 6.41667 | 7.48611 | 18.5816 | 21.6785
1250556 | Existing Garage - Roof Level | 2.89583 | 6.41667 | 7.48611 | 18.5816 | 21.6785
1250557 | Existing Garage - Roof Level | 2.89583 | 6.41667 | 7.48611 | 18.5816 | 21.6785
1253728 | Existing Garage - 1st Level | 2.89583 | 11.8333 | 13.8056 | 34.2674 | 39.9786
1253849 | Existing Garage - 1st Level | 2.89583 | 11.8333 | 13.8056 | 34.2674 | 39.9786
1253999 | Existing Garage - 2nd Level | 2.89583 | 11.8333 | 13.8056 | 34.2674 | 39.9786
1254000 | Existing Garage - 2nd Level | 2.89583 | 11.8333 | 13.8056 | 34.2674 | 39.9786
1254010 | Existing Garage - 3rd Level | 2.89583 | 11.8333 | 13.8056 | 34.2674 | 39.9786
1254011 | Existing Garage - 3rd Level | 2.89583 | 11.8333 | 13.8056 | 34.2674 | 39.9786
1254021 | Existing Garage - 4th Level | 2.89583 | 11.8333 | 13.8056 | 34.2674 | 39.9786
1254022 | Existing Garage - 4th Level | 2.89583 | 11.8333 | 13.8056 | 34.2674 | 39.9786
1254032 | Existing Garage - 5th Level | 2.89583 | 11.8333 | 13.8056 | 34.2674 | 39.9786
1254033 | Existing Garage - 5th Level | 2.89583 | 11.8333 | 13.8056 | 34.2674 | 39.9786
1254043 | Existing Garage - Roof Level | 2.89583 | 11.8333 | 13.8056 | 34.2674 | 39.9786
1254044 | Existing Garage - Roof Level | 2.89583 | 11.8333 | 13.8056 | 34.2674 | 39.9786
1255638 | Exist Garage - Ground Level | 14.25 | 15 | 17.5 | 213.75 | 249.375
1255798 | Exist Garage - Ground Level | 13.3799 | 15 | 17.5 | 200.698 | 234.148
1255880 | Exist Garage - Ground Level | 12.4899 | 15 | 17.5 | 187.349 | 218.573
1255930 | Exist Garage - Ground Level | 11.5898 | 15 | 17.5 | 173.848 | 202.822
1255979 | Exist Garage - Ground Level | 10.6999 | 15 | 17.5 | 160.498 | 187.248
1256041 | Exist Garage - Ground Level | 9.8099 | 15 | 17.5 | 147.148 | 171.673
1256091 | Exist Garage - Ground Level | 8.91992 | 15 | 17.5 | 133.799 | 156.099
1256158 | Exist Garage - Ground Level | 8 | 15 | 17.5 | 120 | 140
1256215 | Exist Garage - Ground Level | 7.13997 | 15 | 17.5 | 107.1 | 124.95

# IfcWallStandardCase: Basic Wall:(existing)Exterior - Brick on Conc - 1'-3" (7)
In: Exist Garage - Ground Level
Type - PredefinedType: STANDARD; Material: Masonry - Brick 0.302083 ft, Misc. Air Layers - Air Space 0.114583 ft, Concrete - Cast-in-Place Concrete_hatch surface 0.833333 ft
Classification: B2010154 Ext. Wall - Brick Cavity (Uniformat)
BaseQuantities - Width: 1.25 ft
Pset_WallCommon - LoadBearing: no; ExtendToStructure: no; IsExternal: yes; Reference: Basic Wall:(existing)Exterior - Brick on Conc - 1'-3"
Name (Basic Wall:(existing)Exterior - Brick on Conc - 1'-3":...) | Height (ft) | Length (ft) | GrossFootprintArea (ft2) | GrossSideArea (ft2) | GrossVolume (ft3)
1235245 | 77.25 | 43.3021 | 54.1276 | 2406.42 | 3008.02
1235388 | 65.8125 | 0.374278 | 0.467848 | 24.6322 | 30.7902
1235717 | 77.25 | 9.41667 | 11.7708 | 727.437 | 909.297
1235773 | 62.25 | 1.48438 | 1.85547 | 92.4023 | 115.503
1242524 | 62.25 | 2 | 2.5 | 124.5 | 155.625
1243008 | 62.25 | 0.916667 | 1.14583 | 57.0625 | 71.3281
1243009 | 62.25 | 2 | 2.5 | 124.5 | 155.625

# IfcWallStandardCase: Basic Wall:(existing)Exterior - Brick on Conc - 1'-6" (2)
In: Exist Garage - Ground Level
Type - PredefinedType: STANDARD; Material: Masonry - Brick 0.302083 ft, Misc. Air Layers - Air Space 0.03125 ft, Concrete - Cast-in-Place Concrete_hatch surface 1.16667 ft
Classification: B2010154 Ext. Wall - Brick Cavity (Uniformat)
BaseQuantities - Height: 12.25 ft; Width: 1.5 ft
Pset_WallCommon - LoadBearing: no; ExtendToStructure: no; IsExternal: yes; Reference: Basic Wall:(existing)Exterior - Brick on Conc - 1'-6"
Name (Basic Wall:(existing)Exterior - Brick on Conc - 1'-6":...) | Length (ft) | GrossFootprintArea (ft2) | GrossSideArea (ft2) | GrossVolume (ft3)
1237055 | 3.22396 | 4.83594 | 39.4935 | 59.2402
1237140 | 8.4935 | 12.7402 | 104.045 | 156.068

# IfcWallStandardCase: Basic Wall:Exterior - Below Grade Conc 12" (6)
In: Exist Garage - Ground Level
Type - PredefinedType: STANDARD; Material: Concrete - Cast-in-Place Concrete 1 ft
Classification: B2010140 Ext. Wall - CMU (Uniformat)
BaseQuantities - Width: 1 ft
Pset_WallCommon - LoadBearing: yes; ExtendToStructure: no; IsExternal: yes; Reference: Basic Wall:Exterior - Below Grade Conc 12"
Name (Basic Wall:Exterior - Below Grade Conc 12":...) | Height (ft) | Length (ft) = GrossFootprintArea (ft2) | GrossSideArea (ft2) = GrossVolume (ft3)
1377685 | 3.27 | 48.9545 | 129.97
1378251 | 3.45711 | 48.5 | 140.852
1384767 | 1.77567 | 37 | 61.3361
1386107 | 2.3687 | 16 | 36.2742
1386145 | 2.13963 | 16 | 32.5386
1457475 | 2.5 | 9.16667 | 22.9167

# IfcWallStandardCase: Basic Wall:Exterior - Below Grade Conc 15" (2)
Type - PredefinedType: STANDARD; Material: Concrete - Cast-in-Place Concrete 1.25 ft
Classification: B2010140 Ext. Wall - CMU (Uniformat)
BaseQuantities - Width: 1.25 ft
Pset_WallCommon - ExtendToStructure: no; IsExternal: yes; Reference: Basic Wall:Exterior - Below Grade Conc 15"
Name (Basic Wall:Exterior - Below Grade Conc 15":...) | In | Height (ft) | Length (ft) | GrossFootprintArea (ft2) | GrossSideArea (ft2) | GrossVolume (ft3) | LoadBearing
1208762 | Exist Garage - Ground Level | 13.05 | 221.25 | 276.562 | 2709.28 | 3386.6 | no
1503788 | Ground Floor | 11.7236 | 73.6667 | 92.0833 | 859.748 | 1074.68 | yes

# IfcWallStandardCase: Basic Wall:Exterior - Below Grade Conc 6" (4)
In: Exist Garage - Ground Level
Type - PredefinedType: STANDARD; Material: Concrete - Cast-in-Place Concrete 0.5 ft
Classification: B2010140 Ext. Wall - CMU (Uniformat)
BaseQuantities - Width: 0.5 ft
Pset_WallCommon - LoadBearing: yes; ExtendToStructure: no; IsExternal: yes; Reference: Basic Wall:Exterior - Below Grade Conc 6"
Name (Basic Wall:Exterior - Below Grade Conc 6":...) | Height (ft) | Length (ft) | GrossFootprintArea (ft2) | GrossSideArea (ft2) | GrossVolume (ft3)
1303257 | 14.25 | 12 | 6 | 171 | 85.5
1303293 | 10.1667 | 30.5 | 15.25 | 310.083 | 155.042
1303314 | 14.25 | 11.5 | 5.75 | 163.875 | 81.9375
1615819 | 10.1667 | 30 | 15 | 305 | 152.5

# IfcWallStandardCase: Basic Wall:Exterior - Conc 6" (6)
Type - PredefinedType: STANDARD; Material: Concrete - Cast-in-Place Concrete 0.5 ft
Classification: B2010140 Ext. Wall - CMU (Uniformat)
BaseQuantities - Width: 0.5 ft
Pset_WallCommon - ExtendToStructure: no; IsExternal: yes; Reference: Basic Wall:Exterior - Conc 6"
Name (Basic Wall:Exterior - Conc 6":...) | In | Height (ft) | Length (ft) | GrossFootprintArea (ft2) | GrossSideArea (ft2) | GrossVolume (ft3) | LoadBearing
1515773 | Existing Garage - Roof Level | 0.666667 | 7 | 3.5 | 4.66667 | 2.33333 | no
1515774 | Existing Garage - Roof Level | 0.666667 | 1.16667 | 0.583333 | 0.777778 | 0.388889 | no
1620845 | Exist Garage - Ground Level | 0.690224 | 20.375 | 10.1875 | 14.0633 | 7.03166 | yes
1620893 | Exist Garage - Ground Level | 0.759594 | 3.5 | 1.75 | 2.65858 | 1.32929 | yes
1620961 | Exist Garage - Ground Level | 0.73723 | 20.375 | 10.1875 | 15.0211 | 7.51053 | yes
1621000 | Exist Garage - Ground Level | 0.713136 | 3.5 | 1.75 | 2.49598 | 1.24799 | yes

# IfcWallStandardCase: Basic Wall:Exterior - Conc 8" (16)
Type - PredefinedType: STANDARD; Material: Concrete - Cast-in-Place Concrete 0.666667 ft
Classification: B2010140 Ext. Wall - CMU (Uniformat)
BaseQuantities - Width: 0.666667 ft
Pset_WallCommon - LoadBearing: yes; ExtendToStructure: no; IsExternal: yes; Reference: Basic Wall:Exterior - Conc 8"
Name (Basic Wall:Exterior - Conc 8":...) | In | Height (ft) | Length (ft) | GrossFootprintArea (ft2) | GrossSideArea (ft2) | GrossVolume (ft3)
1363773 | Exist Garage - Ground Level | 3.91667 | 4.73438 | 3.15625 | 18.543 | 12.362
1363873 | Exist Garage - Ground Level | 3.91667 | 4.5 | 3 | 17.625 | 11.75
1394413 | Existing Garage - 1st Level | 3.33542 | 18.7344 | 12.4896 | 62.4869 | 41.658
1395358 | Existing Garage - 1st Level | 2.88542 | 18 | 12 | 51.9375 | 34.625
1395803 | Existing Garage - 1st Level | 2.88542 | 18 | 12 | 51.9375 | 34.625
1395896 | Existing Garage - 1st Level | 2.88542 | 18 | 12 | 51.9375 | 34.625
1396029 | Existing Garage - 1st Level | 2.88542 | 18 | 12 | 51.9375 | 34.625
1396156 | Existing Garage - 1st Level | 3.05208 | 15 | 10 | 45.7812 | 30.5208
1396318 | Existing Garage - 1st Level | 2.84375 | 15 | 10 | 42.6562 | 28.4375
1397057 | Existing Garage - 2nd Level | 3.38 | 117 | 78 | 395.46 | 263.64
1400353 | Existing Garage - 3rd Level | 3.16 | 117 | 78 | 369.72 | 246.48
1400375 | Existing Garage - 4th Level | 3.16 | 117 | 78 | 369.72 | 246.48
1400391 | Existing Garage - 5th Level | 3.16 | 117 | 78 | 369.72 | 246.48
1400407 | Existing Garage - Roof Level | 3.5 | 121.932 | 81.2882 | 426.763 | 284.509
1405975 | Exist Garage - Ground Level | 3.14583 | 80.4176 | 53.6117 | 252.98 | 168.654
1457476 | Exist Garage - Ground Level | 3.91667 | 7.83334 | 5.22222 | 21.4271 | 14.2847

# IfcWallStandardCase: Basic Wall:Interior - (C12) 12" cmu (17)
In: Exist Garage - Ground Level
Type - PredefinedType: STANDARD; Material: Masonry - Concrete Masonry Units 0.96875 ft
Classification: C1010120 Partitions - CMU (Uniformat)
BaseQuantities - Width: 0.96875 ft
Pset_WallCommon - IsExternal: no; ExtendToStructure: no; Reference: Basic Wall:Interior - (C12) 12" cmu
Name (Basic Wall:Interior - (C12) 12" cmu:...) | Height (ft) | Length (ft) | GrossFootprintArea (ft2) | GrossSideArea (ft2) | GrossVolume (ft3) | LoadBearing
1333020 | 9.49849 | 53 | 51.3438 | 503.42 | 487.688 | no
1333113 | 11.8498 | 16 | 15.5 | 189.597 | 183.672 | no
1333190 | 8.4012 | 53 | 51.3438 | 398.819 | 386.356 | no
1333393 | 11.8498 | 16.3333 | 15.8229 | 169.103 | 163.818 | no
1333461 | 12.1769 | 41.0312 | 39.749 | 499.635 | 484.022 | no
1333544 | 11.8498 | 16 | 15.5 | 165.153 | 159.992 | no
1333776 | 12.25 | 35.0312 | 33.9365 | 336.244 | 325.736 | no
1333925 | 12.0502 | 42 | 40.6875 | 506.11 | 490.295 | no
1333962 | 11.8498 | 16 | 15.5 | 165.153 | 159.992 | no
1357115 | 13.3276 | 22.984 | 22.2658 | 306.322 | 296.75 | yes
1357153 | 13.3276 | 7.25135 | 7.02474 | 96.6431 | 93.623 | yes
1357227 | 10.3576 | 31.2868 | 30.3091 | 117.055 | 113.397 | yes
1357548 | 9.32619 | 16 | 15.5 | 62.9006 | 60.935 | yes
1357699 | 8.90467 | 16 | 15.5 | 58.2222 | 56.4028 | yes
1358246 | 11.1838 | 46.264 | 44.8182 | 283.429 | 274.572 | yes
1358291 | 10.7635 | 28 | 27.125 | 292.378 | 283.241 | yes
1358601 | 7.91558 | 7.23735 | 7.01119 | 56.8302 | 55.0543 | yes

# IfcWallStandardCase: Basic Wall:Interior - (C6) 6" cmu_rated 2 (5)
In: Exist Garage - Ground Level
Type - PredefinedType: STANDARD; Material: Masonry - Concrete Masonry Units_rated 0.46875 ft
Classification: C1010120 Partitions - CMU (Uniformat)
BaseQuantities - Width: 0.46875 ft
Pset_WallCommon - IsExternal: no; LoadBearing: no; ExtendToStructure: no; Reference: Basic Wall:Interior - (C6) 6" cmu_rated 2; FireRating: 2 HR
Name (Basic Wall:Interior - (C6) 6" cmu_rated 2:...) | Height (ft) | Length (ft) | GrossFootprintArea (ft2) | GrossSideArea (ft2) | GrossVolume (ft3)
1624216 | 7.55792 | 4.83333 | 2.26562 | 36.5299 | 17.1234
1625265 | 7.32875 | 14.6667 | 6.875 | 107.488 | 50.3852
1625664 | 6.89125 | 14.6667 | 6.875 | 101.072 | 47.3773
1625789 | 6.44333 | 14.6667 | 6.875 | 94.5022 | 44.2979
1625862 | 6.00583 | 14.6667 | 6.875 | 88.0856 | 41.2901

# IfcWallStandardCase: Basic Wall:Interior - (S4) 2 hour rated shaft wall (3)
In: Exist Garage - Ground Level
Type - PredefinedType: STANDARD; Material: Finishes - Interior - Gypsum Wall Board 0.0833333 ft, Metal - Stud Layer_rated 0.125 ft, Finishes - Interior - Gypsum Wall Board 0.0520833 ft, Finishes - Interior - Gypsum Wall Board 0.0520833 ft
Classification: C1010145 Partitions - Drywall w/ Metal Stud (Uniformat)
BaseQuantities - Width: 0.3125 ft
Pset_WallCommon - IsExternal: no; LoadBearing: no; ExtendToStructure: no; Reference: Basic Wall:Interior - (S4) 2 hour rated shaft wall; FireRating: 2 HR
Name (Basic Wall:Interior - (S4) 2 hour rated shaft wall:...) | Height (ft) | Length (ft) | GrossFootprintArea (ft2) | GrossSideArea (ft2) | GrossVolume (ft3)
1552438 | 1.27995 | 20.7445 | 6.48264 | 26.5518 | 8.29745
1552439 | 3.19792 | 4.75094 | 1.48467 | 15.1931 | 4.74784
1608018 | 2.88542 | 4.75094 | 1.48467 | 13.7084 | 4.28388

# IfcWindow: 5'0" x 6'0" (18)
Type - ParameterTakesPrecedence: no; Sizeable: no; Classification: B2020100 Windows (Uniformat); Material: Glass, Sash
OverallHeight: 6 ft; OverallWidth: 5 ft
Pset_WindowCommon - IsExternal: yes; Reference: Fixed:5'0" x 6'0"
BaseQuantities - Height: 6 ft; Width: 5 ft; Area: 62.7361 ft2
Name (Fixed:5'0" x 6'0":...) | In
1242083 | Existing Garage - 1st Level
1242084 | Existing Garage - 1st Level
1242085 | Existing Garage - 1st Level
1242211 | 2nd Floor
1242212 | 2nd Floor
1242213 | 2nd Floor
1242238 | Existing Garage - 3rd Level
1242239 | Existing Garage - 3rd Level
1242240 | Existing Garage - 3rd Level
1242258 | Existing Garage - 4th Level
1242259 | Existing Garage - 4th Level
1242260 | Existing Garage - 4th Level
1242278 | Existing Garage - 5th Level
1242279 | Existing Garage - 5th Level
1242280 | Existing Garage - 5th Level
1242296 | Existing Garage - Roof Level
1242297 | Existing Garage - Roof Level
1242298 | Existing Garage - Roof Level

# IfcWindow: 5'0" x 8'0" (3)
In: Exist Garage - Ground Level
Type - ParameterTakesPrecedence: no; Sizeable: no; Classification: B2020100 Windows (Uniformat); Material: Glass, Sash
OverallHeight: 8 ft; OverallWidth: 5 ft
Pset_WindowCommon - IsExternal: yes; Reference: Fixed:5'0" x 8'0"
BaseQuantities - Height: 8 ft; Width: 5 ft; Area: 78.8194 ft2
Name (Fixed:5'0" x 8'0":...)
1241842
1242000
1242019

# IfcWindow: 6'4" x 6'0" (6)
Type - ParameterTakesPrecedence: no; Sizeable: no; Classification: B2020100 Windows (Uniformat); Material: Glass, Sash
OverallHeight: 6 ft; OverallWidth: 6.33333 ft
Pset_WindowCommon - IsExternal: yes; Reference: Fixed:6'4" x 6'0"
BaseQuantities - Height: 6 ft; Width: 6.33333 ft; Area: 74.7917 ft2
Name (Fixed:6'4" x 6'0":...) | In
1242082 | Existing Garage - 1st Level
1242210 | 2nd Floor
1242237 | Existing Garage - 3rd Level
1242257 | Existing Garage - 4th Level
1242277 | Existing Garage - 5th Level
1242295 | Existing Garage - Roof Level

# IfcWindow: 6'4" x 8'0", Fixed:6'4" x 8'0":1241742
In: Exist Garage - Ground Level
Type - ParameterTakesPrecedence: no; Sizeable: no; Classification: B2020100 Windows (Uniformat); Material: Glass, Sash
OverallHeight: 8 ft; OverallWidth: 6.33333 ft
Pset_WindowCommon - IsExternal: yes; Reference: Fixed:6'4" x 8'0"
BaseQuantities - Height: 8 ft; Width: 6.33333 ft; Area: 93.5417 ft2
